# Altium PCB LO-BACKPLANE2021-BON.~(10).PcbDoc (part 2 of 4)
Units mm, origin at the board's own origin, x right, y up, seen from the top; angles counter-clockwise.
Board outline 469.9 x 101.6 mm, 4 copper layers (1, Signal Layer 1, Signal Layer 2, 4), stack 1.53 mm thick; 160 components, 92 nets, 524 pads, 8353 vias.

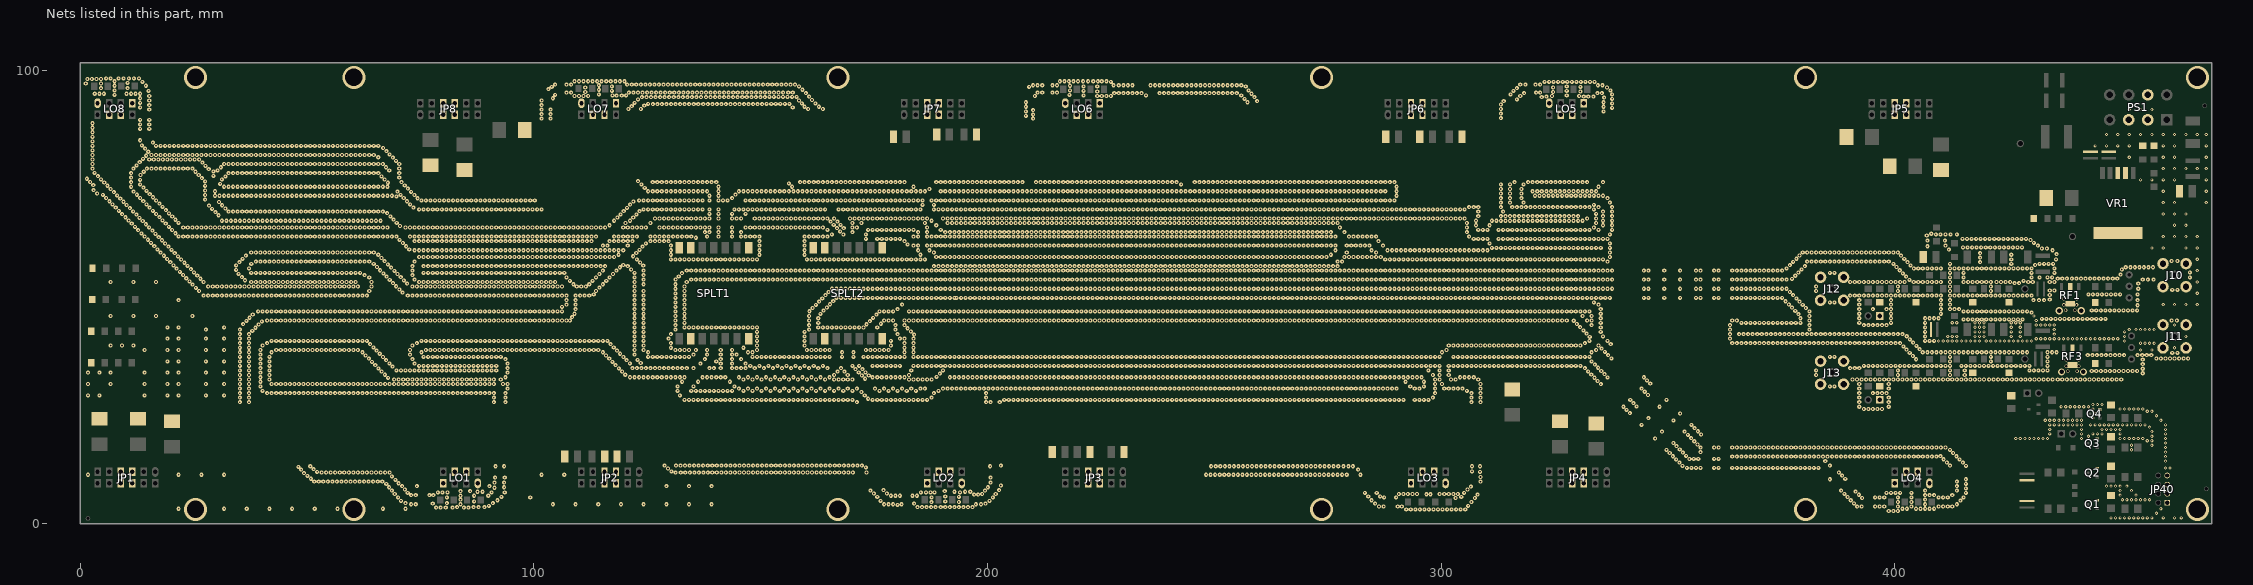
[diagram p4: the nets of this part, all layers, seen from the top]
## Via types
v1: diameter 0.9, hole 0.35, 1 to 4, 7972 vias
v2: diameter 0.7, hole 0.3, 1 to 4, 286 vias
v3: diameter 1.6, hole 1, 1 to 4, 60 vias
v4: diameter 0.762, hole 0.508, 1 to 4, 12 vias
v5: diameter 5.08, hole 3.85, 1 to 4, 12 vias
v6: diameter 2, hole 1.1, 1 to 4, 10 vias
v7: diameter 1.27, hole 0.7, 1 to 4, 1 vias

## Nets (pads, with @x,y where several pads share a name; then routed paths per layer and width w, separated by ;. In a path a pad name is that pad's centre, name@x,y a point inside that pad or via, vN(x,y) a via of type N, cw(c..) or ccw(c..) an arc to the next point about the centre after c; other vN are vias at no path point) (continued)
GND: (continued)
  other v1: 398.7,2.8 399.7,2.8 400.7,2.8 292.325,3.175 293.325,3.175 294.325,3.175 295.325,3.175 296.325,3.175 297.325,3.175 298.325,3.175 299.325,3.175 300.325,3.175 301.325,3.175 302.325,3.175 303.325,3.175 304.325,3.175 305.325,3.175 21.7,3.3 31.7,3.3 36.7,3.3 41.7,3.3 46.7,3.3 51.7,3.3 56.7,3.3 66.7,3.3 71.7,3.3 401.7,3.3 402.7,3.3 404.7,3.3 405.7,3.3 406.7,3.3 407.7,3.3 408.7,3.3 78.45,3.55 79.45,3.55 80.575,3.55 82.075,3.55 84.575,3.55 85.575,3.55 83.075,3.675 86.7,3.675 87.825,3.675 89.075,3.675 184.575,3.675 185.575,3.675 186.575,3.675 187.575,3.675 188.575,3.675 189.7,3.675 190.7,3.675 191.7,3.675 192.7,3.675 193.7,3.675 194.7,3.675 195.7,3.675 196.7,3.675 391.736,3.764 286.325,3.8 287.325,3.8 290.45,3.8 291.325,3.8 392.7,3.8 395.7,3.8 396.7,3.8 397.7,3.8 400.7,3.8 403.7,3.8 409.7,3.8 410.7,3.8 411.7,3.8 412.7,3.8 90.075,3.925 305.95,3.925 180.2,4.175 72.95,4.3 73.95,4.3 83.825,4.3 104.2,4.3 109.2,4.3 114.2,4.3 119.2,4.3 124.2,4.3 129.2,4.3 134.2,4.3 139.2,4.3 177.2,4.3 178.2,4.3 179.2,4.3 181.075,4.3 197.45,4.3 198.575,4.3 406.7,4.3 413.7,4.3 77.7,4.425 183.825,4.425 199.575,4.425 285.45,4.425 391.028,4.472 71.7,4.55 80.825,4.55 90.95,4.55 187.625,4.75 193.7,4.8 306.7,4.8 400.7,4.8 403.7,4.8 86.825,4.925 190.7,4.925 70.7,5.05 176.45,5.05 200.45,5.05 414.493,5.093 91.95,5.175 284.7,5.175 390.321,5.179 83.825,5.3 406.7,5.3 303.2,5.675 307.45,5.675 392.821,5.679 70.075,5.8 80.825,5.8 99.2,5.8 187.7,5.8 201.2,5.8 287.45,5.8 290.075,5.8 395.7,5.8 396.7,5.8 397.7,5.8 400.7,5.8 403.7,5.8 409.7,5.8 410.7,5.8 411.7,5.8 415.2,5.8 389.614,5.886 92.825,5.925 175.7,5.925 193.7,5.925 304.45,5.925 190.7,6.05 283.95,6.05 286.575,6.05 83.825,6.175 86.825,6.175 89.95,6.175 178.7,6.175 179.7,6.175 180.7,6.175 183.45,6.175 184.45,6.175 72.95,6.3 73.95,6.3 76.95,6.3 77.825,6.3 406.7,6.3 407.7,6.3 408.7,6.3 412.7,6.3 392.114,6.386 197.075,6.425 197.95,6.425 308.075,6.425 296.75,6.5 297.625,6.5 69.325,6.55 198.825,6.55 201.825,6.55 290.7,6.55 291.7,6.55 292.7,6.55 293.7,6.55 294.7,6.55 299.7,6.55 300.7,6.55 301.7,6.55 302.7,6.55 303.7,6.55 388.907,6.593 174.95,6.675 177.825,6.675 72.2,6.8 283.2,6.8 285.825,6.8 305.075,6.8 398.2,6.8 399.2,6.8 400.2,6.8 401.2,6.8 403.7,6.8 415.7,6.8 78.825,6.925 79.825,6.925 80.95,6.925 90.7,6.925 93.575,6.925 185.325,6.925 186.45,6.925 187.45,6.925 188.325,6.925 193.95,6.925 87.575,7.05 88.7,7.05 192.7,7.05 195.075,7.05 196.2,7.05 391.407,7.093 83.825,7.175 85.95,7.175 190.575,7.175 68.7,7.3 174.2,7.3 199.45,7.3 388.2,7.3 406.7,7.3 413.7,7.3 177.075,7.425 202.575,7.425 71.575,7.55 305.825,7.55 415.7,7.8 91.325,7.925 68.075,8.05 93.45,8.05 200.075,8.05 306.575,8.175 70.95,8.3 74.2,8.3 90.2,8.3 129.2,8.3 134.2,8.3 139.2,8.3 413.7,8.3 202.95,8.425 67.45,8.8 415.7,8.8 70.2,8.925 91.325,9.05 93.45,9.05 200.7,9.05 51.575,9.3 52.575,9.3 53.575,9.3 54.575,9.3 55.575,9.3 56.575,9.3 57.575,9.3 58.575,9.3 59.575,9.3 60.575,9.3 61.575,9.3 62.575,9.3 63.575,9.3 64.575,9.3 65.575,9.3 66.575,9.3 308.7,9.3 413.7,9.3 69.45,9.675 385.7,9.8 415.7,9.8 389.114,9.886 50.825,9.925 91.45,10.175 93.575,10.175 200.7,10.175 308.7,10.3 68.7,10.425 50.075,10.55 388.407,10.593 1.7,10.8 21.7,10.8 26.7,10.8 31.7,10.8 101.7,10.8 106.7,10.8 248.2,10.8 249.2,10.8 250.2,10.8 251.2,10.8 252.2,10.8 253.2,10.8 254.2,10.8 255.2,10.8 256.2,10.8 257.2,10.8 258.2,10.8 259.2,10.8 260.2,10.8 261.2,10.8 262.2,10.8 263.2,10.8 264.2,10.8 265.2,10.8 266.2,10.8 267.2,10.8 268.2,10.8 269.2,10.8 270.2,10.8 271.2,10.8 272.2,10.8 273.2,10.8 274.2,10.8 275.2,10.8 276.2,10.8 277.2,10.8 278.2,10.8 279.2,10.8 282.2,10.8 49.325,11.175 131.25,11.25 132.375,11.25 133.375,11.25 134.375,11.25 135.375,11.25 136.375,11.25 137.375,11.25 138.375,11.25 53.2,11.3 54.2,11.3 55.2,11.3 56.2,11.3 57.2,11.3 58.2,11.3 59.2,11.3 60.2,11.3 61.2,11.3 62.2,11.3 63.2,11.3 64.2,11.3 65.2,11.3 66.2,11.3 67.2,11.3 68.2,11.3 139.325,11.3 140.325,11.3 141.325,11.3 142.325,11.3 143.325,11.3 144.325,11.3 145.325,11.3 146.325,11.3 147.325,11.3 148.325,11.3 149.325,11.3 150.325,11.3 151.325,11.3 152.325,11.3 153.325,11.3 154.325,11.3 155.325,11.3 156.325,11.3 157.325,11.3 158.325,11.3 159.325,11.3 160.325,11.3 161.325,11.3 162.325,11.3 163.325,11.3 164.325,11.3 165.325,11.3 166.325,11.3 167.325,11.3 168.325,11.3 169.325,11.3 170.325,11.3 173.325,11.3 387.7,11.3 52.2,11.425 308.575,11.425 130.325,11.55 306.825,11.55 48.7,11.925 281.7,11.925 51.45,12.05 129.575,12.175 354.2,12.3 355.2,12.3 356.2,12.3 357.2,12.3 360.2,12.3 361.2,12.3 364.2,12.3 365.2,12.3 366.2,12.3 367.2,12.3 368.2,12.3 369.2,12.3 370.2,12.3 371.2,12.3 372.2,12.3 373.2,12.3 374.2,12.3 375.2,12.3 376.2,12.3 377.2,12.3 378.2,12.3 379.2,12.3 380.2,12.3 381.2,12.3 382.2,12.3 383.2,12.3 173.2,12.425 48.075,12.55 50.7,12.675 91.575,12.675 93.45,12.675 200.575,12.675 249.325,12.675 250.325,12.675 251.325,12.675 252.325,12.675 253.325,12.675 254.325,12.675 255.325,12.675 256.325,12.675 257.325,12.675 258.325,12.675 259.325,12.675 260.325,12.675 261.325,12.675 262.325,12.675 263.325,12.675 264.325,12.675 265.325,12.675 266.325,12.675 267.325,12.675 268.325,12.675 269.325,12.675 270.325,12.675 271.325,12.675 272.325,12.675 273.325,12.675 274.325,12.675 275.325,12.675 276.325,12.675 277.325,12.675 278.45,12.675 279.575,12.675 280.575,12.675 306.825,12.675 308.575,12.675 353.236,12.764 415.736,12.764 128.825,12.8 131.325,12.8 132.325,12.8 133.325,12.8 134.325,12.8 135.325,12.8 136.325,12.8 137.325,12.8 138.325,12.8 139.325,12.8 140.325,12.8 141.325,12.8 142.325,12.8 143.325,12.8 144.325,12.8 145.325,12.8 146.325,12.8 147.325,12.8 148.325,12.8 149.325,12.8 150.325,12.8 151.325,12.8 152.325,12.8 153.325,12.8 154.325,12.8 155.325,12.8 156.325,12.8 157.325,12.8 158.325,12.8 159.325,12.8 160.325,12.8 161.325,12.8 162.325,12.8 163.325,12.8 164.325,12.8 165.325,12.8 166.325,12.8 167.325,12.8 168.325,12.8 169.325,12.8 170.325,12.8 171.325,12.8 172.325,12.8 202.95,12.8 385.7,12.8 412.2,12.8 352.528,13.472 415.028,13.472 411.493,13.507 384.7,13.8 351.821,14.179 414.321,14.179 410.786,14.214 354.736,14.264 355.7,14.3 356.7,14.3 360.2,14.3 361.2,14.3 364.2,14.8 365.2,14.8 366.2,14.8 367.2,14.8 368.2,14.8 369.2,14.8 370.2,14.8 371.2,14.8 372.2,14.8 373.2,14.8 374.2,14.8 375.2,14.8 376.2,14.8 377.2,14.8 378.2,14.8 379.2,14.8 380.2,14.8 381.2,14.8 382.2,14.8 383.2,14.8 384.2,14.8 385.2,14.8 386.2,14.8 387.2,14.8 388.2,14.8 389.2,14.8 390.2,14.8 391.2,14.8 392.2,14.8 393.2,14.8 394.2,14.8 395.2,14.8 396.2,14.8 397.2,14.8 398.2,14.8 399.2,14.8 400.2,14.8 401.2,14.8 402.2,14.8 403.2,14.8 404.2,14.8 405.2,14.8 406.2,14.8 407.2,14.8 408.2,14.8 409.2,14.8 351.114,14.886 413.614,14.886 410.079,14.921 354.028,14.972 350.407,15.593 412.907,15.593 353.321,15.679 357.2,15.8 349.7,16.3 412.2,16.3 352.614,16.386 357.236,16.764 360.2,16.8 361.2,16.8 364.2,16.8 365.2,16.8 366.2,16.8 367.2,16.8 368.2,16.8 369.2,16.8 370.2,16.8 371.2,16.8 372.2,16.8 373.2,16.8 374.2,16.8 375.2,16.8 376.2,16.8 377.2,16.8 378.2,16.8 379.2,16.8 380.2,16.8 381.2,16.8 382.2,16.8 383.2,16.8 384.2,16.8 385.2,16.8 386.2,16.8 387.2,16.8 388.2,16.8 389.2,16.8 390.2,16.8 391.2,16.8 392.2,16.8 393.2,16.8 394.2,16.8 395.2,16.8 396.2,16.8 397.2,16.8 398.2,16.8 399.2,16.8 400.2,16.8 401.2,16.8 402.2,16.8 403.2,16.8 404.2,16.8 405.2,16.8 406.2,16.8 407.2,16.8 408.2,16.8 409.2,16.8 410.2,16.8 411.2,16.8 351.907,17.093 356.528,17.472 351.2,17.8 355.821,18.179 347.2,18.8 355.114,18.886 354.407,19.593 357.321,19.679 348.7,20.3 353.7,20.3 356.614,20.386 355.907,21.093 344.2,21.8 355.2,21.8 351.2,22.8 345.7,23.3 352.7,24.3 341.614,24.386 340.907,25.093 393.2,25.3 394.2,25.3 395.2,25.3 396.2,25.3 397.2,25.3 340.2,25.8 348.2,25.8 392.2,25.8 398.7,25.8 343.114,25.886 342.407,26.593 35.2,26.8 37.2,26.8 91.2,26.8 93.7,26.8 171.2,26.8 199.7,26.8 200.7,26.8 202.7,26.8 392.2,26.8 398.7,26.8 306.7,26.825 308.7,26.825 133.2,27.3 134.2,27.3 135.2,27.3 136.2,27.3 137.2,27.3 138.2,27.3 139.2,27.3 140.2,27.3 141.2,27.3 142.2,27.3 143.2,27.3 144.2,27.3 145.2,27.3 146.2,27.3 147.2,27.3 148.2,27.3 149.2,27.3 150.2,27.3 151.2,27.3 152.2,27.3 153.2,27.3 154.2,27.3 155.2,27.3 156.2,27.3 157.2,27.3 158.2,27.3 159.2,27.3 160.2,27.3 161.2,27.3 162.2,27.3 163.2,27.3 164.2,27.3 165.2,27.3 166.2,27.3 167.2,27.3 168.2,27.3 169.2,27.3 170.2,27.3 174.7,27.3 175.7,27.3 176.7,27.3 177.7,27.3 178.7,27.3 179.7,27.3 180.7,27.3 181.7,27.3 182.7,27.3 183.7,27.3 184.7,27.3 185.7,27.3 186.7,27.3 203.7,27.3 204.7,27.3 205.7,27.3 206.7,27.3 207.7,27.3 208.7,27.3 209.7,27.3 210.7,27.3 211.7,27.3 212.7,27.3 213.7,27.3 214.7,27.3 215.7,27.3 216.7,27.3 217.7,27.3 218.7,27.3 219.7,27.3 220.7,27.3 221.7,27.3 222.7,27.3 223.7,27.3 224.7,27.3 225.7,27.3 226.7,27.3 227.7,27.3 228.7,27.3 229.7,27.3 230.7,27.3 231.7,27.3 232.7,27.3 233.7,27.3 234.7,27.3 235.7,27.3 236.7,27.3 237.7,27.3 238.7,27.3 239.7,27.3 240.7,27.3 241.7,27.3 242.7,27.3 243.7,27.3 244.7,27.3 245.7,27.3 246.7,27.3 247.7,27.3 248.7,27.3 249.7,27.3 250.7,27.3 251.7,27.3 252.7,27.3 253.7,27.3 254.7,27.3 255.7,27.3 256.7,27.3 257.7,27.3 258.7,27.3 259.7,27.3 260.7,27.3 261.7,27.3 262.7,27.3 263.7,27.3 264.7,27.3 265.7,27.3 266.7,27.3 267.7,27.3 268.7,27.3 269.7,27.3 270.7,27.3 271.7,27.3 272.7,27.3 273.7,27.3 274.7,27.3 275.7,27.3 276.7,27.3 277.7,27.3 278.7,27.3 279.7,27.3 280.7,27.3 281.7,27.3 282.7,27.3 283.7,27.3 284.7,27.3 285.7,27.3 286.7,27.3 287.7,27.3 288.7,27.3 289.7,27.3 290.7,27.3 291.7,27.3 294.2,27.3 295.2,27.3 296.2,27.3 297.2,27.3 341.7,27.3 349.7,27.3 173.7,27.55 35.2,27.8 37.2,27.8 91.2,27.8 93.7,27.8 187.7,27.8 199.7,27.8 298.2,27.8 306.7,27.8 308.7,27.8 392.2,27.8 398.7,27.8 1.7,28.3 4.2,28.3 14.2,28.3 19.2,28.3 21.7,28.3 27.7,28.3 31.7,28.3 132.2,28.3 172.95,28.3 345.614,28.386 35.2,28.8 37.2,28.8 41.2,28.8 42.2,28.8 43.2,28.8 44.2,28.8 45.2,28.8 46.2,28.8 47.2,28.8 48.2,28.8 49.2,28.8 50.2,28.8 51.2,28.8 52.2,28.8 53.2,28.8 54.2,28.8 55.2,28.8 56.2,28.8 57.2,28.8 58.2,28.8 59.2,28.8 60.2,28.8 61.2,28.8 62.2,28.8 63.2,28.8 64.2,28.8 65.2,28.8 66.2,28.8 67.2,28.8 68.2,28.8 69.2,28.8 70.2,28.8 71.2,28.8 72.2,28.8 73.2,28.8 74.2,28.8 75.2,28.8 76.2,28.8 77.2,28.8 78.2,28.8 79.2,28.8 80.2,28.8 81.2,28.8 82.2,28.8 83.2,28.8 84.2,28.8 85.2,28.8 86.2,28.8 87.2,28.8 88.2,28.8 89.2,28.8 90.2,28.8 91.2,28.8 93.7,28.8 188.2,28.8 199.7,28.8 298.7,28.8 306.7,28.8 308.7,28.8 392.2,28.8 395.2,28.8 396.2,28.8 397.2,28.8 398.2,28.8 172.2,29.05 344.907,29.093 40.2,29.3 131.7,29.3 134.7,29.3 135.7,29.3 136.7,29.3 137.7,29.3 138.7,29.3 139.7,29.3 140.7,29.3 141.7,29.3 142.7,29.3 143.7,29.3 146.2,29.3 148.2,29.3 150.2,29.3 152.2,29.3 154.2,29.3 156.2,29.3 158.2,29.3 160.2,29.3 162.2,29.3 164.2,29.3 166.2,29.3 168.2,29.3 170.2,29.3 176.2,29.3 178.2,29.3 180.2,29.3 182.2,29.3 184.2,29.3 189.2,29.3 305.7,29.3 35.2,29.8 37.2,29.8 94.2,29.8 145.2,29.8 147.2,29.8 149.2,29.8 151.2,29.8 153.2,29.8 155.2,29.8 157.2,29.8 159.2,29.8 161.2,29.8 163.2,29.8 165.2,29.8 167.2,29.8 169.2,29.8 171.2,29.8 175.2,29.8 177.2,29.8 179.2,29.8 181.2,29.8 183.2,29.8 185.2,29.8 186.2,29.8 190.2,29.8 191.2,29.8 192.2,29.8 193.2,29.8 194.2,29.8 195.2,29.8 196.2,29.8 197.2,29.8 198.2,29.8 199.2,29.8 200.2,29.8 201.2,29.8 202.2,29.8 203.2,29.8 204.2,29.8 205.2,29.8 206.2,29.8 207.2,29.8 208.2,29.8 209.2,29.8 210.2,29.8 211.2,29.8 212.2,29.8 213.2,29.8 214.2,29.8 215.2,29.8 216.2,29.8 217.2,29.8 218.2,29.8 219.2,29.8 220.2,29.8 221.2,29.8 222.2,29.8 223.2,29.8 224.2,29.8 225.2,29.8 226.2,29.8 227.2,29.8 228.2,29.8 229.2,29.8 230.2,29.8 231.2,29.8 232.2,29.8 233.2,29.8 234.2,29.8 235.2,29.8 236.2,29.8 237.2,29.8 238.2,29.8 239.2,29.8 240.2,29.8 241.2,29.8 242.2,29.8 243.2,29.8 244.2,29.8 245.2,29.8 246.2,29.8 247.2,29.8 248.2,29.8 249.2,29.8 250.2,29.8 251.2,29.8 252.2,29.8 253.2,29.8 254.2,29.8 255.2,29.8 256.2,29.8 257.2,29.8 258.2,29.8 259.2,29.8 260.2,29.8 261.2,29.8 262.2,29.8 263.2,29.8 264.2,29.8 265.2,29.8 266.2,29.8 267.2,29.8 268.2,29.8 269.2,29.8 270.2,29.8 271.2,29.8 272.2,29.8 273.2,29.8 274.2,29.8 275.2,29.8 276.2,29.8 277.2,29.8 278.2,29.8 279.2,29.8 280.2,29.8 281.2,29.8 282.2,29.8 283.2,29.8 284.2,29.8 285.2,29.8 286.2,29.8 287.2,29.8 288.2,29.8 289.2,29.8 290.2,29.8 294.2,29.8 295.2,29.8 298.7,29.8 300.7,29.8 301.7,29.8 302.7,29.8 303.7,29.8 304.7,29.8 308.7,29.8 344.2,29.8 392.2,29.8 398.7,29.8 39.7,30.3 131.7,30.3 135.2,30.3 144.2,30.3 293.2,30.3 296.2,30.3 385.7,30.3 386.7,30.3 335.236,30.764 1.7,30.8 6.7,30.8 14.2,30.8 19.2,30.8 21.7,30.8 27.7,30.8 31.7,30.8 35.2,30.8 37.2,30.8 42.2,30.8 43.2,30.8 44.2,30.8 45.2,30.8 46.2,30.8 47.2,30.8 48.2,30.8 49.2,30.8 50.2,30.8 51.2,30.8 52.2,30.8 53.2,30.8 54.2,30.8 55.2,30.8 56.2,30.8 57.2,30.8 58.2,30.8 59.2,30.8 60.2,30.8 61.2,30.8 62.2,30.8 63.2,30.8 64.2,30.8 65.2,30.8 66.2,30.8 67.2,30.8 68.2,30.8 69.2,30.8 70.2,30.8 71.2,30.8 72.2,30.8 73.2,30.8 74.2,30.8 75.2,30.8 76.2,30.8 77.2,30.8 78.2,30.8 79.2,30.8 80.2,30.8 81.2,30.8 82.2,30.8 83.2,30.8 84.2,30.8 85.2,30.8 86.2,30.8 87.2,30.8 88.2,30.8 89.2,30.8 90.2,30.8 91.2,30.8 93.2,30.8 94.2,30.8 298.7,30.8 300.2,30.8 308.7,30.8 392.2,30.8 398.7,30.8 346.114,30.886 39.7,31.3 132.7,31.3 136.2,31.3 143.2,31.3 292.2,31.3 296.2,31.3 334.528,31.472 345.407,31.593 35.2,31.8 37.2,31.8 41.7,31.8 69.2,31.8 70.2,31.8 71.2,31.8 72.2,31.8 73.2,31.8 74.2,31.8 75.2,31.8 76.2,31.8 77.2,31.8 78.2,31.8 79.2,31.8 80.2,31.8 81.2,31.8 82.2,31.8 83.2,31.8 84.2,31.8 85.2,31.8 86.2,31.8 87.2,31.8 88.2,31.8 89.2,31.8 90.2,31.8 91.2,31.8 92.7,31.8 146.2,31.8 148.2,31.8 150.2,31.8 152.2,31.8 154.2,31.8 156.2,31.8 158.2,31.8 160.2,31.8 162.2,31.8 164.2,31.8 166.2,31.8 167.2,31.8 168.2,31.8 169.2,31.8 170.2,31.8 182.7,31.8 183.7,31.8 184.7,31.8 185.7,31.8 186.7,31.8 187.7,31.8 298.7,31.8 299.7,31.8 302.2,31.8 303.2,31.8 308.2,31.8 390.7,31.8 391.7,31.8 392.7,31.8 393.7,31.8 394.7,31.8 395.7,31.8 396.7,31.8 397.7,31.8 398.7,31.8 399.7,31.8 400.7,31.8 401.7,31.8 402.7,31.8 403.7,31.8 404.7,31.8 405.7,31.8 406.7,31.8 407.7,31.8 408.7,31.8 409.7,31.8 410.7,31.8 411.7,31.8 412.7,31.8 413.7,31.8 414.7,31.8 415.7,31.8 416.7,31.8 417.7,31.8 418.7,31.8 419.7,31.8 420.825,31.8 421.825,31.8 422.825,31.8 423.825,31.8 424.825,31.8 425.825,31.8 426.825,31.8 427.825,31.8 428.825,31.8 429.825,31.8 430.825,31.8 431.825,31.8 432.825,31.8 433.825,31.8 434.825,31.8 435.95,31.8 436.95,31.8 437.95,31.8 438.95,31.8 439.95,31.8 440.95,31.8 441.95,31.8 442.95,31.8 443.95,31.8 444.95,31.8 445.95,31.8 446.95,31.8 447.95,31.8 448.95,31.8 449.95,31.8 173.028,31.972 67.857,32.143 333.821,32.179 336.736,32.264 39.7,32.3 93.7,32.3 121.2,32.3 122.2,32.3 123.2,32.3 124.2,32.3 125.2,32.3 126.2,32.3 127.2,32.3 128.2,32.3 129.2,32.3 130.2,32.3 131.2,32.3 132.2,32.3 133.2,32.3 137.2,32.3 138.2,32.3 139.2,32.3 140.2,32.3 141.2,32.3 142.2,32.3 145.2,32.3 147.2,32.3 149.2,32.3 151.2,32.3 153.2,32.3 155.2,32.3 157.2,32.3 159.2,32.3 161.2,32.3 163.2,32.3 165.2,32.3 174.7,32.3 175.7,32.3 176.7,32.3 177.7,32.3 178.7,32.3 179.7,32.3 180.7,32.3 181.7,32.3 191.7,32.3 192.7,32.3 193.7,32.3 194.7,32.3 195.7,32.3 196.7,32.3 197.7,32.3 198.7,32.3 199.7,32.3 200.7,32.3 201.7,32.3 202.7,32.3 203.7,32.3 204.7,32.3 205.7,32.3 206.7,32.3 207.7,32.3 208.7,32.3 209.7,32.3 210.7,32.3 211.7,32.3 212.7,32.3 213.7,32.3 214.7,32.3 215.7,32.3 216.7,32.3 217.7,32.3 218.7,32.3 219.7,32.3 220.7,32.3 221.7,32.3 222.7,32.3 223.7,32.3 224.7,32.3 225.7,32.3 226.7,32.3 227.7,32.3 228.7,32.3 229.7,32.3 230.7,32.3 231.7,32.3 232.7,32.3 233.7,32.3 234.7,32.3 235.7,32.3 236.7,32.3 237.7,32.3 238.7,32.3 239.7,32.3 240.7,32.3 241.7,32.3 242.7,32.3 243.7,32.3 244.7,32.3 245.7,32.3 246.7,32.3 247.7,32.3 248.7,32.3 249.7,32.3 250.7,32.3 251.7,32.3 252.7,32.3 253.7,32.3 254.7,32.3 255.7,32.3 256.7,32.3 257.7,32.3 258.7,32.3 259.7,32.3 260.7,32.3 261.7,32.3 262.7,32.3 263.7,32.3 264.7,32.3 265.7,32.3 266.7,32.3 267.7,32.3 268.7,32.3 269.7,32.3 270.7,32.3 271.7,32.3 272.7,32.3 273.7,32.3 274.7,32.3 275.7,32.3 276.7,32.3 277.7,32.3 278.7,32.3 279.7,32.3 280.7,32.3 281.7,32.3 282.7,32.3 283.7,32.3 284.7,32.3 285.7,32.3 286.7,32.3 287.7,32.3 288.7,32.3 289.7,32.3 290.7,32.3 291.7,32.3 292.7,32.3 293.7,32.3 294.7,32.3 295.7,32.3 304.2,32.3 305.2,32.3 306.2,32.3 307.2,32.3 344.7,32.3 188.786,32.386 172.321,32.679 173.821,32.679 35.2,32.8 37.2,32.8 41.7,32.8 166.2,32.8 169.2,32.8 182.7,32.8 298.2,32.8 299.7,32.8 301.7,32.8 382.7,32.8 400.7,32.8 412.2,32.8 415.45,32.8 67.15,32.85 120.15,32.85 333.114,32.886 336.028,32.972 189.493,33.093 454.7,33.175 1.7,33.3 4.2,33.3 6.7,33.3 14.2,33.3 19.2,33.3 21.7,33.3 27.7,33.3 31.7,33.3 39.7,33.3 94.2,33.3 171.614,33.386 173.114,33.386 66.443,33.557 119.443,33.557 166.95,33.55 168.45,33.55 332.407,33.593 335.321,33.679 443.45,33.675 444.45,33.675 445.45,33.675 446.45,33.675 447.45,33.675 448.45,33.675 449.45,33.675 450.45,33.675 451.45,33.675 452.45,33.675 453.45,33.675 35.2,33.8 37.2,33.8 41.7,33.8 69.7,33.8 70.7,33.8 71.7,33.8 72.7,33.8 73.7,33.8 74.7,33.8 75.7,33.8 76.7,33.8 77.7,33.8 78.7,33.8 79.7,33.8 80.7,33.8 81.7,33.8 82.7,33.8 83.7,33.8 84.7,33.8 85.7,33.8 86.7,33.8 87.7,33.8 88.7,33.8 89.7,33.8 90.7,33.8 91.7,33.8 183.2,33.8 190.2,33.8 297.2,33.8 299.7,33.8 301.7,33.8 382.7,33.8 400.7,33.8 412.2,33.8 415.45,33.8 429.7,33.8 430.7,33.8 431.7,33.8 432.7,33.8 433.7,33.8 170.907,34.093 172.407,34.093 454.7,34.175 65.736,34.264 118.736,34.264 39.7,34.3 94.2,34.3 121.7,34.3 122.7,34.3 123.7,34.3 124.7,34.3 125.7,34.3 126.7,34.3 127.7,34.3 128.7,34.3 129.7,34.3 130.7,34.3 131.7,34.3 132.7,34.3 133.7,34.3 135.2,34.3 138.7,34.3 139.7,34.3 141.2,34.3 143.7,34.3 144.7,34.3 145.7,34.3 146.7,34.3 148.7,34.3 150.7,34.3 152.7,34.3 154.7,34.3 156.7,34.3 158.7,34.3 160.7,34.3 162.7,34.3 164.7,34.3 167.7,34.3 331.7,34.3 390.2,34.3 391.2,34.3 392.2,34.3 334.614,34.386 68.857,34.643 35.2,34.8 37.2,34.8 41.7,34.8 74.7,34.8 75.7,34.8 76.7,34.8 77.7,34.8 78.7,34.8 79.7,34.8 80.7,34.8 81.7,34.8 82.7,34.8 83.7,34.8 84.7,34.8 85.7,34.8 86.7,34.8 87.7,34.8 88.7,34.8 89.7,34.8 90.7,34.8 91.7,34.8 147.7,34.8 149.7,34.8 151.7,34.8 153.7,34.8 155.7,34.8 157.7,34.8 159.7,34.8 161.7,34.8 163.7,34.8 170.2,34.8 171.7,34.8 174.7,34.8 175.7,34.8 176.7,34.8 177.7,34.8 178.7,34.8 179.7,34.8 180.7,34.8 183.7,34.8 184.7,34.8 185.7,34.8 186.7,34.8 187.7,34.8 188.7,34.8 189.7,34.8 190.7,34.8 191.7,34.8 192.7,34.8 193.7,34.8 194.7,34.8 195.7,34.8 196.7,34.8 197.7,34.8 198.7,34.8 199.7,34.8 200.7,34.8 201.7,34.8 202.7,34.8 203.7,34.8 204.7,34.8 205.7,34.8 206.7,34.8 207.7,34.8 208.7,34.8 209.7,34.8 210.7,34.8 211.7,34.8 212.7,34.8 213.7,34.8 214.7,34.8 215.7,34.8 216.7,34.8 217.7,34.8 218.7,34.8 219.7,34.8 220.7,34.8 221.7,34.8 222.7,34.8 223.7,34.8 224.7,34.8 225.7,34.8 226.7,34.8 227.7,34.8 228.7,34.8 229.7,34.8 230.7,34.8 231.7,34.8 232.7,34.8 233.7,34.8 234.7,34.8 235.7,34.8 236.7,34.8 237.7,34.8 238.7,34.8 239.7,34.8 240.7,34.8 241.7,34.8 242.7,34.8 243.7,34.8 244.7,34.8 245.7,34.8 246.7,34.8 247.7,34.8 248.7,34.8 249.7,34.8 250.7,34.8 251.7,34.8 252.7,34.8 253.7,34.8 254.7,34.8 255.7,34.8 256.7,34.8 257.7,34.8 258.7,34.8 259.7,34.8 260.7,34.8 261.7,34.8 262.7,34.8 263.7,34.8 264.7,34.8 265.7,34.8 266.7,34.8 267.7,34.8 268.7,34.8 269.7,34.8 270.7,34.8 271.7,34.8 272.7,34.8 273.7,34.8 274.7,34.8 275.7,34.8 276.7,34.8 277.7,34.8 278.7,34.8 279.7,34.8 280.7,34.8 281.7,34.8 282.7,34.8 283.7,34.8 284.7,34.8 285.7,34.8 286.7,34.8 287.7,34.8 288.7,34.8 289.7,34.8 290.7,34.8 291.7,34.8 292.7,34.8 293.7,34.8 294.7,34.8 295.7,34.8 296.7,34.8 297.7,34.8 298.7,34.8 299.7,34.8 301.7,34.8 302.7,34.8 303.7,34.8 304.7,34.8 305.7,34.8 306.7,34.8 307.7,34.8 308.7,34.8 309.7,34.8 310.7,34.8 311.7,34.8 312.7,34.8 313.7,34.8 314.7,34.8 315.7,34.8 316.7,34.8 317.7,34.8 318.7,34.8 319.7,34.8 320.7,34.8 321.7,34.8 322.7,34.8 323.7,34.8 324.7,34.8 325.7,34.8 326.7,34.8 327.7,34.8 328.7,34.8 329.7,34.8 330.7,34.8 393.2,34.8 394.2,34.8 395.2,34.8 396.2,34.8 397.2,34.8 398.2,34.8 399.2,34.8 400.2,34.8 401.2,34.8 402.2,34.8 403.2,34.8 404.2,34.8 405.2,34.8 406.2,34.8 407.2,34.8 408.2,34.8 409.2,34.8 410.2,34.8 411.2,34.8 412.2,34.8 414.7,34.8 415.7,34.8 416.7,34.8 417.7,34.8 418.7,34.8 419.7,34.8 420.7,34.8 421.7,34.8 422.7,34.8 423.7,34.8 424.7,34.8 425.7,34.8 426.7,34.8 427.7,34.8 428.7,34.8 429.7,34.8 433.7,34.8 65.028,34.972 118.028,34.972 333.907,35.093 454.7,35.175 39.7,35.3 73.7,35.3 94.2,35.3 136.7,35.3 141.2,35.3 143.7,35.3 146.7,35.3 68.15,35.35 121.15,35.35 123.564,35.436 64.321,35.679 117.321,35.679 19.2,35.8 21.7,35.8 27.7,35.8 31.7,35.8 35.2,35.8 37.2,35.8 41.7,35.8 140.2,35.8 333.2,35.8 412.2,35.8 421.2,35.8 433.7,35.8 67.443,36.057 120.443,36.057 122.857,36.143 454.7,36.175 404.736,36.264 39.7,36.3 73.2,36.3 93.7,36.3 137.7,36.3 141.2,36.3 143.7,36.3 145.7,36.3 63.614,36.386 116.614,36.386 457.7,36.425 458.7,36.425 459.7,36.425 460.7,36.425 461.7,36.425 462.7,36.425 463.7,36.425 464.7,36.425 337.528,36.472 66.736,36.764 119.736,36.764 35.2,36.8 37.2,36.8 41.7,36.8 75.7,36.8 76.7,36.8 77.7,36.8 78.7,36.8 79.7,36.8 80.7,36.8 81.7,36.8 82.7,36.8 83.7,36.8 84.7,36.8 85.7,36.8 86.7,36.8 87.7,36.8 88.7,36.8 89.7,36.8 90.7,36.8 91.7,36.8 92.7,36.8 125.2,36.8 126.2,36.8 127.2,36.8 128.2,36.8 129.2,36.8 130.2,36.8 131.2,36.8 132.2,36.8 133.2,36.8 134.2,36.8 148.2,36.8 149.2,36.8 150.2,36.8 151.2,36.8 152.2,36.8 153.2,36.8 154.2,36.8 155.2,36.8 156.2,36.8 157.2,36.8 158.2,36.8 159.2,36.8 160.2,36.8 161.2,36.8 162.2,36.8 163.2,36.8 164.2,36.8 165.2,36.8 167.95,36.8 170.45,36.8 172.7,36.8 173.7,36.8 174.7,36.8 175.7,36.8 176.7,36.8 177.7,36.8 178.7,36.8 179.7,36.8 180.7,36.8 181.7,36.8 183.7,36.8 184.7,36.8 185.7,36.8 186.7,36.8 187.7,36.8 188.7,36.8 189.7,36.8 190.7,36.8 191.7,36.8 192.7,36.8 193.7,36.8 194.7,36.8 195.7,36.8 196.7,36.8 197.7,36.8 198.7,36.8 199.7,36.8 200.7,36.8 201.7,36.8 202.7,36.8 203.7,36.8 204.7,36.8 205.7,36.8 206.7,36.8 207.7,36.8 208.7,36.8 209.7,36.8 210.7,36.8 211.7,36.8 212.7,36.8 213.7,36.8 214.7,36.8 215.7,36.8 216.7,36.8 217.7,36.8 218.7,36.8 219.7,36.8 220.7,36.8 221.7,36.8 222.7,36.8 223.7,36.8 224.7,36.8 225.7,36.8 226.7,36.8 227.7,36.8 228.7,36.8 229.7,36.8 230.7,36.8 231.7,36.8 232.7,36.8 233.7,36.8 234.7,36.8 235.7,36.8 236.7,36.8 237.7,36.8 238.7,36.8 239.7,36.8 240.7,36.8 241.7,36.8 242.7,36.8 243.7,36.8 244.7,36.8 245.7,36.8 246.7,36.8 247.7,36.8 248.7,36.8 249.7,36.8 250.7,36.8 251.7,36.8 252.7,36.8 253.7,36.8 254.7,36.8 255.7,36.8 256.7,36.8 257.7,36.8 258.7,36.8 259.7,36.8 260.7,36.8 261.7,36.8 262.7,36.8 263.7,36.8 264.7,36.8 265.7,36.8 266.7,36.8 267.7,36.8 268.7,36.8 269.7,36.8 270.7,36.8 271.7,36.8 272.7,36.8 273.7,36.8 274.7,36.8 275.7,36.8 276.7,36.8 277.7,36.8 278.7,36.8 279.7,36.8 280.7,36.8 281.7,36.8 282.7,36.8 283.7,36.8 284.7,36.8 285.7,36.8 286.7,36.8 287.7,36.8 288.7,36.8 289.7,36.8 290.7,36.8 291.7,36.8 292.7,36.8 293.7,36.8 294.7,36.8 295.7,36.8 296.7,36.8 297.7,36.8 298.7,36.8 299.7,36.8 302.7,36.8 303.7,36.8 304.7,36.8 305.7,36.8 306.7,36.8 307.7,36.8 308.7,36.8 309.7,36.8 310.7,36.8 311.7,36.8 312.7,36.8 313.7,36.8 314.7,36.8 315.7,36.8 316.7,36.8 317.7,36.8 318.7,36.8 319.7,36.8 320.7,36.8 321.7,36.8 322.7,36.8 323.7,36.8 324.7,36.8 325.7,36.8 326.7,36.8 327.7,36.8 328.7,36.8 329.7,36.8 330.7,36.8 331.7,36.8 332.7,36.8 385.7,36.8 386.7,36.8 412.2,36.8 421.2,36.8 433.7,36.8 404.028,36.972 62.907,37.093 115.907,37.093 336.821,37.179 442.575,37.175 443.575,37.175 444.575,37.175 445.575,37.175 446.575,37.175 447.575,37.175 448.575,37.175 449.575,37.175 450.575,37.175 453.575,37.175 454.575,37.175 455.575,37.175 456.575,37.175 39.7,37.3 72.7,37.3 122.2,37.3 135.2,37.3 138.2,37.3 141.2,37.3 143.7,37.3 144.7,37.3 66.028,37.472 119.028,37.472 403.321,37.679 461.2,37.675 462.325,37.675 35.2,37.8 37.2,37.8 42.2,37.8 62.2,37.8 75.2,37.8 115.2,37.8 125.2,37.8 147.2,37.8 148.2,37.8 167.95,37.8 170.45,37.8 181.7,37.8 183.7,37.8 300.2,37.8 333.2,37.8 406.2,37.8 407.2,37.8 408.2,37.8 409.2,37.8 410.2,37.8 411.2,37.8 412.2,37.8 413.2,37.8 414.2,37.8 415.2,37.8 416.2,37.8 417.2,37.8 418.2,37.8 419.2,37.8 420.2,37.8 421.2,37.8 422.2,37.8 423.2,37.8 424.2,37.8 425.2,37.8 426.2,37.8 427.2,37.8 428.2,37.8 429.2,37.8 433.7,37.8 434.7,37.8 435.7,37.8 336.114,37.886 65.321,38.179 118.321,38.179 14.2,38.3 19.2,38.3 21.7,38.3 27.7,38.3 31.7,38.3 39.7,38.3 43.2,38.3 44.2,38.3 45.2,38.3 46.2,38.3 47.2,38.3 48.2,38.3 49.2,38.3 50.2,38.3 51.2,38.3 52.2,38.3 53.2,38.3 54.2,38.3 55.2,38.3 56.2,38.3 57.2,38.3 58.2,38.3 59.2,38.3 60.2,38.3 61.2,38.3 72.7,38.3 76.2,38.3 77.2,38.3 78.2,38.3 79.2,38.3 80.2,38.3 81.2,38.3 82.2,38.3 83.2,38.3 84.2,38.3 85.2,38.3 86.2,38.3 87.2,38.3 88.2,38.3 89.2,38.3 90.2,38.3 91.2,38.3 92.2,38.3 93.2,38.3 94.2,38.3 95.2,38.3 96.2,38.3 97.2,38.3 98.2,38.3 99.2,38.3 100.2,38.3 101.2,38.3 102.2,38.3 103.2,38.3 104.2,38.3 105.2,38.3 106.2,38.3 107.2,38.3 108.2,38.3 109.2,38.3 110.2,38.3 111.2,38.3 112.2,38.3 113.2,38.3 114.2,38.3 122.2,38.3 124.2,38.3 131.2,38.3 132.2,38.3 133.2,38.3 134.2,38.3 135.7,38.3 138.2,38.3 141.2,38.3 143.7,38.3 149.2,38.3 160.2,38.3 161.2,38.3 162.2,38.3 163.2,38.3 164.2,38.3 165.2,38.3 173.2,38.3 174.2,38.3 175.2,38.3 176.2,38.3 177.2,38.3 178.2,38.3 301.2,38.3 334.2,38.3 402.614,38.386 405.493,38.507 335.407,38.593 35.2,38.8 37.2,38.8 130.2,38.8 146.2,38.8 181.7,38.8 183.7,38.8 64.614,38.886 117.614,38.886 401.907,39.093 404.786,39.214 6.7,39.3 9.2,39.3 11.7,39.3 40.2,39.3 73.2,39.3 122.2,39.3 124.2,39.3 149.2,39.3 159.7,39.3 178.7,39.3 301.7,39.3 302.7,39.3 303.7,39.3 304.7,39.3 305.7,39.3 306.7,39.3 307.7,39.3 308.7,39.3 309.7,39.3 310.7,39.3 311.7,39.3 312.7,39.3 313.7,39.3 314.7,39.3 315.7,39.3 316.7,39.3 317.7,39.3 318.7,39.3 319.7,39.3 320.7,39.3 321.7,39.3 322.7,39.3 323.7,39.3 324.7,39.3 325.7,39.3 326.7,39.3 327.7,39.3 328.7,39.3 329.7,39.3 330.7,39.3 334.7,39.3 63.907,39.593 116.907,39.593 337.407,39.593 35.2,39.8 37.2,39.8 41.2,39.8 74.2,39.8 130.2,39.8 181.7,39.8 183.7,39.8 331.7,39.8 364.2,39.8 365.2,39.8 366.2,39.8 367.2,39.8 368.2,39.8 369.2,39.8 370.2,39.8 371.2,39.8 372.2,39.8 373.2,39.8 374.2,39.8 375.2,39.8 376.2,39.8 377.2,39.8 378.2,39.8 379.2,39.8 380.2,39.8 381.2,39.8 382.2,39.8 383.2,39.8 384.2,39.8 385.2,39.8 386.2,39.8 387.2,39.8 388.2,39.8 389.2,39.8 390.2,39.8 391.2,39.8 392.2,39.8 393.2,39.8 394.2,39.8 395.2,39.8 396.2,39.8 397.2,39.8 398.2,39.8 399.2,39.8 400.2,39.8 401.2,39.8 404.079,39.921 42.2,40.3 43.2,40.3 44.2,40.3 45.2,40.3 46.2,40.3 47.2,40.3 48.2,40.3 49.2,40.3 50.2,40.3 51.2,40.3 52.2,40.3 53.2,40.3 54.2,40.3 55.2,40.3 56.2,40.3 57.2,40.3 58.2,40.3 59.2,40.3 60.2,40.3 61.2,40.3 62.2,40.3 63.2,40.3 75.2,40.3 76.2,40.3 77.2,40.3 78.2,40.3 79.2,40.3 80.2,40.3 81.2,40.3 82.2,40.3 83.2,40.3 84.2,40.3 85.2,40.3 86.2,40.3 87.2,40.3 88.2,40.3 89.2,40.3 90.2,40.3 91.2,40.3 92.2,40.3 93.2,40.3 94.2,40.3 95.2,40.3 96.2,40.3 97.2,40.3 98.2,40.3 99.2,40.3 100.2,40.3 101.2,40.3 102.2,40.3 103.2,40.3 104.2,40.3 105.2,40.3 106.2,40.3 107.2,40.3 108.2,40.3 109.2,40.3 110.2,40.3 111.2,40.3 112.2,40.3 113.2,40.3 114.2,40.3 115.2,40.3 116.2,40.3 122.2,40.3 124.2,40.3 149.2,40.3 159.7,40.3 178.7,40.3 332.7,40.3 336.7,40.3 406.7,40.3 407.7,40.3 408.7,40.3 403.372,40.628 19.2,40.8 21.7,40.8 27.7,40.8 31.7,40.8 35.2,40.8 37.2,40.8 129.7,40.8 180.7,40.8 181.7,40.8 183.7,40.8 363.7,40.8 332.786,41.214 122.2,41.3 124.2,41.3 149.2,41.3 159.7,41.3 335.7,41.3 406.7,41.3 402.664,41.336 183.821,41.679 35.2,41.8 37.2,41.8 130.2,41.8 180.2,41.8 363.7,41.8 365.7,41.8 366.7,41.8 367.7,41.8 368.7,41.8 369.7,41.8 370.7,41.8 371.7,41.8 372.7,41.8 373.7,41.8 374.7,41.8 375.7,41.8 376.7,41.8 377.7,41.8 378.7,41.8 379.7,41.8 380.7,41.8 381.7,41.8 382.7,41.8 383.7,41.8 384.7,41.8 385.7,41.8 386.7,41.8 387.7,41.8 388.7,41.8 389.7,41.8 390.7,41.8 391.7,41.8 392.7,41.8 393.7,41.8 394.7,41.8 395.7,41.8 396.7,41.8 397.7,41.8 398.7,41.8 399.7,41.8 400.7,41.8 401.7,41.8 332.079,41.921 122.2,42.3 124.2,42.3 149.2,42.3 159.7,42.3 335.2,42.3 406.7,42.3 183.114,42.386 37.907,42.507 331.372,42.628 27.7,42.8 35.2,42.8 131.2,42.8 160.7,42.8 179.7,42.8 363.7,42.8 381.2,42.8 182.407,43.093 38.614,43.214 172.664,43.264 19.2,43.3 21.7,43.3 31.7,43.3 122.2,43.3 124.2,43.3 133.2,43.3 134.2,43.3 135.2,43.3 136.2,43.3 137.2,43.3 138.2,43.3 139.2,43.3 140.2,43.3 141.2,43.3 142.2,43.3 143.2,43.3 144.2,43.3 145.2,43.3 146.2,43.3 147.2,43.3 148.2,43.3 149.2,43.3 162.7,43.3 163.7,43.3 164.7,43.3 165.7,43.3 166.7,43.3 167.7,43.3 168.7,43.3 169.7,43.3 170.7,43.3 171.7,43.3 175.7,43.3 335.2,43.3 406.7,43.3 330.664,43.336 131.2,43.8 160.7,43.8 179.7,43.8 181.7,43.8 333.2,43.8 363.7,43.8 381.2,43.8 393.2,43.8 394.2,43.8 395.2,43.8 396.2,43.8 397.2,43.8 398.2,43.8 39.321,43.921 173.372,43.972 35.907,44.007 329.957,44.043 176.493,44.093 122.2,44.3 124.2,44.3 133.2,44.3 162.7,44.3 335.2,44.3 366.2,44.3 367.2,44.3 368.2,44.3 369.2,44.3 370.2,44.3 371.2,44.3 372.2,44.3 373.2,44.3 374.2,44.3 375.2,44.3 376.2,44.3 377.2,44.3 378.2,44.3 379.2,44.3 392.2,44.3 399.2,44.3 406.7,44.3 40.028,44.628 174.079,44.679 36.614,44.714 329.25,44.75 41.2,44.8 42.2,44.8 43.2,44.8 44.2,44.8 45.2,44.8 46.2,44.8 47.2,44.8 48.2,44.8 49.2,44.8 50.2,44.8 51.2,44.8 52.2,44.8 53.2,44.8 54.2,44.8 55.2,44.8 56.2,44.8 57.2,44.8 58.2,44.8 59.2,44.8 60.2,44.8 61.2,44.8 62.2,44.8 63.2,44.8 64.2,44.8 65.2,44.8 66.2,44.8 67.2,44.8 68.2,44.8 69.2,44.8 70.2,44.8 71.2,44.8 72.2,44.8 73.2,44.8 74.2,44.8 75.2,44.8 76.2,44.8 77.2,44.8 78.2,44.8 79.2,44.8 80.2,44.8 81.2,44.8 82.2,44.8 83.2,44.8 84.2,44.8 85.2,44.8 86.2,44.8 87.2,44.8 88.2,44.8 89.2,44.8 90.2,44.8 91.2,44.8 92.2,44.8 93.2,44.8 94.2,44.8 95.2,44.8 96.2,44.8 97.2,44.8 98.2,44.8 99.2,44.8 100.2,44.8 101.2,44.8 102.2,44.8 103.2,44.8 104.2,44.8 105.2,44.8 106.2,44.8 107.2,44.8 107.95,44.8 131.2,44.8 160.7,44.8 177.2,44.8 178.2,44.8 179.2,44.8 181.7,44.8 182.7,44.8 183.7,44.8 184.7,44.8 185.7,44.8 186.7,44.8 187.7,44.8 188.7,44.8 189.7,44.8 190.7,44.8 191.7,44.8 192.7,44.8 193.7,44.8 194.7,44.8 195.7,44.8 196.7,44.8 197.7,44.8 198.7,44.8 199.7,44.8 200.7,44.8 201.7,44.8 202.7,44.8 203.7,44.8 204.7,44.8 205.7,44.8 206.7,44.8 207.7,44.8 208.7,44.8 209.7,44.8 210.7,44.8 211.7,44.8 212.7,44.8 213.7,44.8 214.7,44.8 215.7,44.8 216.7,44.8 217.7,44.8 218.7,44.8 219.7,44.8 220.7,44.8 221.7,44.8 222.7,44.8 223.7,44.8 224.7,44.8 225.7,44.8 226.7,44.8 227.7,44.8 228.7,44.8 229.7,44.8 230.7,44.8 231.7,44.8 232.7,44.8 233.7,44.8 234.7,44.8 235.7,44.8 236.7,44.8 237.7,44.8 238.7,44.8 239.7,44.8 240.7,44.8 241.7,44.8 242.7,44.8 243.7,44.8 244.7,44.8 245.7,44.8 246.7,44.8 247.7,44.8 248.7,44.8 249.7,44.8 250.7,44.8 251.7,44.8 252.7,44.8 253.7,44.8 254.7,44.8 255.7,44.8 256.7,44.8 257.7,44.8 258.7,44.8 259.7,44.8 260.7,44.8 261.7,44.8 262.7,44.8 263.7,44.8 264.7,44.8 265.7,44.8 266.7,44.8 267.7,44.8 268.7,44.8 269.7,44.8 270.7,44.8 271.7,44.8 272.7,44.8 273.7,44.8 274.7,44.8 275.7,44.8 276.7,44.8 277.7,44.8 278.7,44.8 279.7,44.8 280.7,44.8 281.7,44.8 282.7,44.8 283.7,44.8 284.7,44.8 285.7,44.8 286.7,44.8 287.7,44.8 288.7,44.8 289.7,44.8 290.7,44.8 291.7,44.8 292.7,44.8 293.7,44.8 294.7,44.8 295.7,44.8 296.7,44.8 297.7,44.8 298.7,44.8 299.7,44.8 300.7,44.8 301.7,44.8 302.7,44.8 303.7,44.8 304.7,44.8 305.7,44.8 306.7,44.8 307.7,44.8 308.7,44.8 309.7,44.8 310.7,44.8 311.7,44.8 312.7,44.8 313.7,44.8 314.7,44.8 315.7,44.8 316.7,44.8 317.7,44.8 318.7,44.8 319.7,44.8 320.7,44.8 321.7,44.8 322.7,44.8 323.7,44.8 324.7,44.8 325.7,44.8 326.7,44.8 327.7,44.8 332.2,44.8 333.2,44.8 364.2,44.8 365.2,44.8 381.2,44.8 461.075,44.8 462.2,44.8 415.2,45.05 416.2,45.05 417.2,45.05 418.2,45.05 419.2,45.05 420.2,45.05 421.2,45.05 422.2,45.05 423.2,45.05 424.2,45.05 425.2,45.05 426.2,45.05 427.2,45.05 428.2,45.05 432.45,45.175 433.45,45.175 434.45,45.175 435.45,45.175 436.45,45.175 437.45,45.175 438.45,45.175 439.45,45.175 440.45,45.175 441.45,45.175 442.45,45.175 443.45,45.175 444.45,45.175 445.45,45.175 446.45,45.175 122.2,45.3 124.2,45.3 133.2,45.3 162.7,45.3 335.2,45.3 379.2,45.3 392.2,45.3 399.2,45.3 406.7,45.3 407.7,45.3 408.7,45.3 409.7,45.3 174.786,45.386 37.321,45.421 108.45,45.55 6.7,45.8 11.7,45.8 16.7,45.8 24.7,45.8 131.2,45.8 160.7,45.8 331.2,45.8 333.2,45.8 381.2,45.8 175.493,46.093 38.028,46.128 378.786,46.214 163.164,46.264 108.95,46.3 122.2,46.3 124.2,46.3 133.2,46.3 335.2,46.3 392.2,46.3 399.2,46.3 410.2,46.3 430.2,46.55 39.2,46.8 40.2,46.8 41.2,46.8 42.2,46.8 43.2,46.8 44.2,46.8 45.2,46.8 46.2,46.8 47.2,46.8 48.2,46.8 49.2,46.8 50.2,46.8 51.2,46.8 52.2,46.8 53.2,46.8 54.2,46.8 55.2,46.8 56.2,46.8 57.2,46.8 58.2,46.8 59.2,46.8 60.2,46.8 61.2,46.8 62.2,46.8 63.2,46.8 64.2,46.8 65.2,46.8 66.2,46.8 67.2,46.8 68.2,46.8 69.2,46.8 70.2,46.8 71.2,46.8 72.2,46.8 73.2,46.8 74.2,46.8 75.2,46.8 76.2,46.8 77.2,46.8 78.2,46.8 79.2,46.8 80.2,46.8 81.2,46.8 82.2,46.8 83.2,46.8 84.2,46.8 85.2,46.8 86.2,46.8 87.2,46.8 88.2,46.8 89.2,46.8 90.2,46.8 91.2,46.8 92.2,46.8 93.2,46.8 94.2,46.8 95.2,46.8 96.2,46.8 97.2,46.8 98.2,46.8 99.2,46.8 100.2,46.8 101.2,46.8 102.2,46.8 103.2,46.8 104.2,46.8 105.2,46.8 106.2,46.8 131.2,46.8 176.2,46.8 177.2,46.8 178.2,46.8 179.2,46.8 182.7,46.8 183.7,46.8 184.7,46.8 185.7,46.8 186.7,46.8 187.7,46.8 188.7,46.8 189.7,46.8 190.7,46.8 191.7,46.8 192.7,46.8 193.7,46.8 194.7,46.8 195.7,46.8 196.7,46.8 197.7,46.8 198.7,46.8 199.7,46.8 200.7,46.8 201.7,46.8 202.7,46.8 203.7,46.8 204.7,46.8 205.7,46.8 206.7,46.8 207.7,46.8 208.7,46.8 209.7,46.8 210.7,46.8 211.7,46.8 212.7,46.8 213.7,46.8 214.7,46.8 215.7,46.8 216.7,46.8 217.7,46.8 218.7,46.8 219.7,46.8 220.7,46.8 221.7,46.8 222.7,46.8 223.7,46.8 224.7,46.8 225.7,46.8 226.7,46.8 227.7,46.8 228.7,46.8 229.7,46.8 230.7,46.8 231.7,46.8 232.7,46.8 233.7,46.8 234.7,46.8 235.7,46.8 236.7,46.8 237.7,46.8 238.7,46.8 239.7,46.8 240.7,46.8 241.7,46.8 242.7,46.8 243.7,46.8 244.7,46.8 245.7,46.8 246.7,46.8 247.7,46.8 248.7,46.8 249.7,46.8 250.7,46.8 251.7,46.8 252.7,46.8 253.7,46.8 254.7,46.8 255.7,46.8 256.7,46.8 257.7,46.8 258.7,46.8 259.7,46.8 260.7,46.8 261.7,46.8 262.7,46.8 263.7,46.8 264.7,46.8 265.7,46.8 266.7,46.8 267.7,46.8 268.7,46.8 269.7,46.8 270.7,46.8 271.7,46.8 272.7,46.8 273.7,46.8 274.7,46.8 275.7,46.8 276.7,46.8 277.7,46.8 278.7,46.8 279.7,46.8 280.7,46.8 281.7,46.8 282.7,46.8 283.7,46.8 284.7,46.8 285.7,46.8 286.7,46.8 287.7,46.8 288.7,46.8 289.7,46.8 290.7,46.8 291.7,46.8 292.7,46.8 293.7,46.8 294.7,46.8 295.7,46.8 296.7,46.8 297.7,46.8 298.7,46.8 299.7,46.8 300.7,46.8 301.7,46.8 302.7,46.8 303.7,46.8 304.7,46.8 305.7,46.8 306.7,46.8 307.7,46.8 308.7,46.8 309.7,46.8 310.7,46.8 311.7,46.8 312.7,46.8 313.7,46.8 314.7,46.8 315.7,46.8 316.7,46.8 317.7,46.8 318.7,46.8 319.7,46.8 320.7,46.8 321.7,46.8 322.7,46.8 323.7,46.8 324.7,46.8 325.7,46.8 326.7,46.8 327.7,46.8 328.7,46.8 329.7,46.8 330.7,46.8 331.7,46.8 332.7,46.8 381.2,46.8 415.2,46.8 416.2,46.8 417.2,46.8 418.2,46.8 419.2,46.8 420.2,46.8 421.2,46.8 422.2,46.8 423.2,46.8 424.2,46.8 425.2,46.8 426.2,46.8 427.2,46.8 428.2,46.8 429.2,46.8 160.75,46.85 378.079,46.921 163.872,46.972 443.45,47.05 444.45,47.05 445.45,47.05 446.45,47.05 447.45,47.05 448.45,47.05 449.45,47.05 450.45,47.05 451.45,47.05 452.45,47.05 453.45,47.05 109.2,47.3 122.2,47.3 124.2,47.3 133.2,47.3 180.2,47.3 335.2,47.3 392.2,47.3 395.2,47.3 398.2,47.3 399.2,47.3 410.2,47.3 412.2,47.3 413.2,47.3 414.2,47.3 161.457,47.557 380.443,47.557 377.372,47.628 164.579,47.679 106.2,47.8 131.2,47.8 453.575,48.175 162.164,48.264 379.736,48.264 107.2,48.3 109.2,48.3 122.2,48.3 124.2,48.3 133.2,48.3 181.2,48.3 334.7,48.3 392.2,48.3 399.2,48.3 410.2,48.3 412.2,48.3 376.664,48.336 165.286,48.386 131.2,48.8 333.7,48.8 385.7,48.8 386.7,48.8 162.872,48.972 379.028,48.972 375.957,49.043 165.993,49.093 21.7,49.3 107.2,49.3 109.2,49.3 122.2,49.3 124.2,49.3 133.2,49.3 392.2,49.3 399.2,49.3 410.2,49.3 412.2,49.3 430.575,49.3 431.825,49.3 432.95,49.3 453.575,49.3 434.2,49.425 163.579,49.679 378.321,49.679 131.2,49.8 166.7,49.8 167.7,49.8 168.7,49.8 169.7,49.8 170.7,49.8 171.7,49.8 172.7,49.8 173.7,49.8 174.7,49.8 175.7,49.8 176.7,49.8 177.7,49.8 178.7,49.8 179.7,49.8 180.7,49.8 181.7,49.8 182.7,49.8 183.7,49.8 184.7,49.8 185.7,49.8 186.7,49.8 187.7,49.8 188.7,49.8 189.7,49.8 190.7,49.8 191.7,49.8 192.7,49.8 193.2,49.8 194.2,49.8 195.2,49.8 196.2,49.8 197.2,49.8 198.2,49.8 199.2,49.8 200.2,49.8 201.2,49.8 202.2,49.8 203.2,49.8 204.2,49.8 205.2,49.8 206.2,49.8 207.2,49.8 208.2,49.8 209.2,49.8 210.2,49.8 211.2,49.8 212.2,49.8 213.2,49.8 214.2,49.8 215.2,49.8 216.2,49.8 217.2,49.8 218.2,49.8 219.2,49.8 220.2,49.8 221.2,49.8 222.2,49.8 223.2,49.8 224.2,49.8 225.2,49.8 226.2,49.8 227.2,49.8 228.2,49.8 229.2,49.8 230.2,49.8 231.2,49.8 232.2,49.8 233.2,49.8 234.2,49.8 235.2,49.8 236.2,49.8 237.2,49.8 238.2,49.8 239.2,49.8 240.2,49.8 241.2,49.8 242.2,49.8 243.2,49.8 244.2,49.8 245.2,49.8 246.2,49.8 247.2,49.8 248.2,49.8 249.2,49.8 250.2,49.8 251.2,49.8 252.2,49.8 253.2,49.8 254.2,49.8 255.2,49.8 256.2,49.8 257.2,49.8 258.2,49.8 259.2,49.8 260.2,49.8 261.2,49.8 262.2,49.8 263.2,49.8 264.2,49.8 265.2,49.8 266.2,49.8 267.2,49.8 268.2,49.8 269.2,49.8 270.2,49.8 271.2,49.8 272.2,49.8 273.2,49.8 274.2,49.8 275.2,49.8 276.2,49.8 277.2,49.8 278.2,49.8 279.2,49.8 280.2,49.8 281.2,49.8 282.2,49.8 283.2,49.8 284.2,49.8 285.2,49.8 286.2,49.8 287.2,49.8 288.2,49.8 289.2,49.8 290.2,49.8 291.2,49.8 292.2,49.8 293.2,49.8 294.2,49.8 295.2,49.8 296.2,49.8 297.2,49.8 298.2,49.8 299.2,49.8 300.2,49.8 301.2,49.8 302.2,49.8 303.2,49.8 304.2,49.8 305.2,49.8 306.2,49.8 307.2,49.8 308.2,49.8 309.2,49.8 310.2,49.8 311.2,49.8 312.2,49.8 313.2,49.8 314.2,49.8 315.2,49.8 316.2,49.8 317.2,49.8 318.2,49.8 319.2,49.8 320.2,49.8 321.2,49.8 322.2,49.8 323.2,49.8 324.2,49.8 325.2,49.8 326.2,49.8 327.2,49.8 328.2,49.8 329.2,49.8 330.2,49.8 331.2,49.8 332.2,49.8 333.2,49.8 334.2,49.8 335.2,49.8 336.2,49.8 337.2,49.8 344.7,49.8 345.7,49.8 349.2,49.8 352.7,49.8 356.2,49.8 357.2,49.8 360.2,49.8 361.2,49.8 364.2,49.8 365.2,49.8 366.2,49.8 367.2,49.8 368.2,49.8 369.2,49.8 370.2,49.8 371.2,49.8 372.2,49.8 373.2,49.8 374.2,49.8 375.2,49.8 27.2,50.3 28.2,50.3 29.2,50.3 30.2,50.3 31.2,50.3 32.2,50.3 33.2,50.3 34.2,50.3 35.2,50.3 36.2,50.3 37.2,50.3 38.2,50.3 39.2,50.3 40.2,50.3 41.2,50.3 42.2,50.3 43.2,50.3 44.2,50.3 45.2,50.3 46.2,50.3 47.2,50.3 48.2,50.3 49.2,50.3 50.2,50.3 51.2,50.3 52.2,50.3 53.2,50.3 54.2,50.3 55.2,50.3 56.2,50.3 57.2,50.3 58.2,50.3 59.2,50.3 60.2,50.3 61.2,50.3 62.2,50.3 63.2,50.3 72.2,50.3 73.2,50.3 74.2,50.3 75.2,50.3 76.2,50.3 77.2,50.3 78.2,50.3 79.2,50.3 80.2,50.3 81.2,50.3 82.2,50.3 83.2,50.3 84.2,50.3 85.2,50.3 86.2,50.3 87.2,50.3 88.2,50.3 89.2,50.3 90.2,50.3 91.2,50.3 92.2,50.3 93.2,50.3 94.2,50.3 95.2,50.3 96.2,50.3 97.2,50.3 98.2,50.3 99.2,50.3 100.2,50.3 101.2,50.3 102.2,50.3 103.2,50.3 104.2,50.3 105.2,50.3 106.2,50.3 107.2,50.3 109.2,50.3 110.2,50.3 111.2,50.3 112.2,50.3 122.2,50.3 124.2,50.3 133.2,50.3 390.2,50.3 391.2,50.3 392.2,50.3 393.2,50.3 394.2,50.3 395.2,50.3 396.2,50.3 397.2,50.3 398.2,50.3 399.2,50.3 400.2,50.3 401.2,50.3 402.2,50.3 403.2,50.3 404.2,50.3 405.2,50.3 406.2,50.3 407.2,50.3 408.2,50.3 409.2,50.3 410.2,50.3 412.2,50.3 413.2,50.3 414.2,50.3 415.2,50.3 416.2,50.3 417.2,50.3 418.2,50.3 419.2,50.3 420.2,50.3 421.2,50.3 422.2,50.3 423.2,50.3 424.2,50.3 425.2,50.3 426.2,50.3 427.2,50.3 428.2,50.3 429.2,50.3 430.2,50.3 164.286,50.386 377.614,50.386 434.2,50.425 113.2,50.55 442.7,50.55 443.7,50.55 444.7,50.55 445.7,50.55 446.7,50.55 447.7,50.55 448.7,50.55 449.7,50.55 453.575,50.55 131.2,50.8 71.064,50.936 164.993,51.093 376.907,51.093 26.2,51.3 63.7,51.3 113.7,51.3 122.2,51.3 124.2,51.3 133.2,51.3 382.7,51.3 400.7,51.3 412.2,51.3 421.2,51.3 434.2,51.425 435.2,51.425 461.2,51.55 462.325,51.55 70.357,51.643 131.2,51.8 165.7,51.8 166.7,51.8 167.7,51.8 168.7,51.8 169.7,51.8 170.7,51.8 171.7,51.8 172.7,51.8 173.7,51.8 174.7,51.8 175.7,51.8 176.7,51.8 177.7,51.8 178.7,51.8 179.7,51.8 180.7,51.8 181.7,51.8 182.7,51.8 183.7,51.8 184.7,51.8 185.7,51.8 186.7,51.8 187.7,51.8 188.7,51.8 189.7,51.8 190.7,51.8 191.7,51.8 192.7,51.8 193.7,51.8 194.7,51.8 195.7,51.8 196.7,51.8 197.7,51.8 198.7,51.8 199.7,51.8 200.7,51.8 201.7,51.8 202.7,51.8 203.7,51.8 204.7,51.8 205.7,51.8 206.7,51.8 207.7,51.8 208.7,51.8 209.7,51.8 210.7,51.8 211.7,51.8 212.7,51.8 213.7,51.8 214.7,51.8 215.7,51.8 216.7,51.8 217.7,51.8 218.7,51.8 219.7,51.8 220.7,51.8 221.7,51.8 222.7,51.8 223.7,51.8 224.7,51.8 225.7,51.8 226.7,51.8 227.7,51.8 228.7,51.8 229.7,51.8 230.7,51.8 231.7,51.8 232.7,51.8 233.7,51.8 234.7,51.8 235.7,51.8 236.7,51.8 237.7,51.8 238.7,51.8 239.7,51.8 240.7,51.8 241.7,51.8 242.7,51.8 243.7,51.8 244.7,51.8 245.7,51.8 246.7,51.8 247.7,51.8 248.7,51.8 249.7,51.8 250.7,51.8 251.7,51.8 252.7,51.8 253.7,51.8 254.7,51.8 255.7,51.8 256.7,51.8 257.7,51.8 258.7,51.8 259.7,51.8 260.7,51.8 261.7,51.8 262.7,51.8 263.7,51.8 264.7,51.8 265.7,51.8 266.7,51.8 267.7,51.8 268.7,51.8 269.7,51.8 270.7,51.8 271.7,51.8 272.7,51.8 273.7,51.8 274.7,51.8 275.7,51.8 276.7,51.8 277.7,51.8 278.7,51.8 279.7,51.8 280.7,51.8 281.7,51.8 282.7,51.8 283.7,51.8 284.7,51.8 285.7,51.8 286.7,51.8 287.7,51.8 288.7,51.8 289.7,51.8 290.7,51.8 291.7,51.8 292.7,51.8 293.7,51.8 294.7,51.8 295.7,51.8 296.7,51.8 297.7,51.8 298.7,51.8 299.7,51.8 300.7,51.8 301.7,51.8 302.7,51.8 303.7,51.8 304.7,51.8 305.7,51.8 306.7,51.8 307.7,51.8 308.7,51.8 309.7,51.8 310.7,51.8 311.7,51.8 312.7,51.8 313.7,51.8 314.7,51.8 315.7,51.8 316.7,51.8 317.7,51.8 318.7,51.8 319.7,51.8 320.7,51.8 321.7,51.8 322.7,51.8 323.7,51.8 324.7,51.8 325.7,51.8 326.7,51.8 327.7,51.8 328.7,51.8 329.7,51.8 330.7,51.8 331.7,51.8 332.7,51.8 333.7,51.8 334.7,51.8 335.7,51.8 336.7,51.8 337.7,51.8 344.7,51.8 345.7,51.8 349.2,51.8 352.7,51.8 356.2,51.8 357.2,51.8 360.2,51.8 361.2,51.8 364.2,51.8 365.2,51.8 366.2,51.8 367.2,51.8 368.2,51.8 369.2,51.8 370.2,51.8 371.2,51.8 372.2,51.8 373.2,51.8 374.2,51.8 375.2,51.8 376.2,51.8 453.7,51.8 25.493,52.007 114.45,52.05 28.2,52.3 29.2,52.3 30.2,52.3 31.2,52.3 32.2,52.3 33.2,52.3 34.2,52.3 35.2,52.3 36.2,52.3 37.2,52.3 38.2,52.3 39.2,52.3 40.2,52.3 41.2,52.3 42.2,52.3 43.2,52.3 44.2,52.3 45.2,52.3 46.2,52.3 47.2,52.3 48.2,52.3 49.2,52.3 50.2,52.3 51.2,52.3 52.2,52.3 53.2,52.3 54.2,52.3 55.2,52.3 56.2,52.3 57.2,52.3 58.2,52.3 59.2,52.3 60.2,52.3 61.2,52.3 64.2,52.3 73.2,52.3 74.2,52.3 75.2,52.3 76.2,52.3 77.2,52.3 78.2,52.3 79.2,52.3 80.2,52.3 81.2,52.3 82.2,52.3 83.2,52.3 84.2,52.3 85.2,52.3 86.2,52.3 87.2,52.3 88.2,52.3 89.2,52.3 90.2,52.3 91.2,52.3 92.2,52.3 93.2,52.3 94.2,52.3 95.2,52.3 96.2,52.3 97.2,52.3 98.2,52.3 99.2,52.3 100.2,52.3 101.2,52.3 102.2,52.3 103.2,52.3 104.2,52.3 105.2,52.3 106.2,52.3 109.45,52.3 110.45,52.3 111.45,52.3 122.2,52.3 133.2,52.3 382.7,52.3 400.7,52.3 412.2,52.3 421.2,52.3 69.65,52.35 24.786,52.714 108.7,52.8 112.2,52.8 115.2,52.8 124.2,52.8 131.2,52.8 72.064,52.936 453.7,52.925 68.943,53.057 426.45,53.05 427.45,53.05 6.7,53.3 11.7,53.3 16.7,53.3 27.2,53.3 37.7,53.3 38.7,53.3 39.7,53.3 40.7,53.3 41.7,53.3 42.7,53.3 43.7,53.3 44.7,53.3 45.7,53.3 46.7,53.3 47.7,53.3 48.7,53.3 49.7,53.3 50.7,53.3 51.7,53.3 52.7,53.3 53.7,53.3 54.7,53.3 55.7,53.3 56.7,53.3 57.7,53.3 58.7,53.3 59.7,53.3 60.7,53.3 64.2,53.3 74.7,53.3 75.7,53.3 76.7,53.3 77.7,53.3 78.7,53.3 79.7,53.3 80.7,53.3 81.7,53.3 82.7,53.3 83.7,53.3 84.7,53.3 85.7,53.3 86.7,53.3 87.7,53.3 88.7,53.3 89.7,53.3 90.7,53.3 91.7,53.3 92.7,53.3 93.7,53.3 94.7,53.3 95.7,53.3 96.7,53.3 97.7,53.3 98.7,53.3 99.7,53.3 100.7,53.3 101.7,53.3 102.7,53.3 103.7,53.3 104.7,53.3 122.2,53.3 133.7,53.3 390.2,53.3 391.2,53.3 392.2,53.3 393.2,53.3 394.2,53.3 395.2,53.3 396.2,53.3 397.2,53.3 398.2,53.3 399.2,53.3 400.2,53.3 401.2,53.3 402.2,53.3 404.2,53.3 405.2,53.3 406.2,53.3 407.2,53.3 408.2,53.3 409.2,53.3 410.2,53.3 412.2,53.3 415.2,53.3 416.2,53.3 417.2,53.3 418.2,53.3 419.2,53.3 420.2,53.3 421.2,53.3 422.45,53.3 423.45,53.3 424.45,53.3 425.45,53.3 429.45,53.3 430.45,53.3 434.2,53.3 435.2,53.3 24.079,53.421 107.95,53.55 112.95,53.55 115.95,53.55 428.45,53.55 71.357,53.643 36.321,53.679 68.236,53.764 403.236,53.764 73.7,53.8 124.2,53.8 134.7,53.8 135.7,53.8 136.7,53.8 137.7,53.8 138.7,53.8 139.7,53.8 140.7,53.8 141.7,53.8 142.7,53.8 143.7,53.8 144.7,53.8 145.7,53.8 146.7,53.8 147.7,53.8 148.7,53.8 149.7,53.8 150.7,53.8 151.7,53.8 152.7,53.8 153.7,53.8 154.7,53.8 155.7,53.8 156.7,53.8 157.7,53.8 158.7,53.8 159.7,53.8 160.7,53.8 161.7,53.8 162.7,53.8 163.7,53.8 164.7,53.8 165.7,53.8 166.7,53.8 167.7,53.8 168.7,53.8 169.7,53.8 170.7,53.8 171.7,53.8 172.7,53.8 173.7,53.8 174.7,53.8 175.7,53.8 176.7,53.8 177.7,53.8 178.7,53.8 179.7,53.8 180.7,53.8 181.7,53.8 182.7,53.8 183.7,53.8 184.7,53.8 185.7,53.8 186.7,53.8 187.7,53.8 188.7,53.8 189.7,53.8 190.7,53.8 191.7,53.8 192.7,53.8 193.7,53.8 194.7,53.8 195.7,53.8 196.7,53.8 197.7,53.8 198.7,53.8 199.7,53.8 200.7,53.8 201.7,53.8 202.7,53.8 203.7,53.8 204.7,53.8 205.7,53.8 206.7,53.8 207.7,53.8 208.7,53.8 209.7,53.8 210.7,53.8 211.7,53.8 212.7,53.8 213.7,53.8 214.7,53.8 215.7,53.8 216.7,53.8 217.7,53.8 218.7,53.8 219.7,53.8 220.7,53.8 221.7,53.8 222.7,53.8 223.7,53.8 224.7,53.8 225.7,53.8 226.7,53.8 227.7,53.8 228.7,53.8 229.7,53.8 230.7,53.8 231.7,53.8 232.7,53.8 233.7,53.8 234.7,53.8 235.7,53.8 236.7,53.8 237.7,53.8 238.7,53.8 239.7,53.8 240.7,53.8 241.7,53.8 242.7,53.8 243.7,53.8 244.7,53.8 245.7,53.8 246.7,53.8 247.7,53.8 248.7,53.8 249.7,53.8 250.7,53.8 251.7,53.8 252.7,53.8 253.7,53.8 254.7,53.8 255.7,53.8 256.7,53.8 257.7,53.8 258.7,53.8 259.7,53.8 260.7,53.8 261.7,53.8 262.7,53.8 263.7,53.8 264.7,53.8 265.7,53.8 266.7,53.8 267.7,53.8 268.7,53.8 269.7,53.8 270.7,53.8 271.7,53.8 272.7,53.8 273.7,53.8 274.7,53.8 275.7,53.8 276.7,53.8 277.7,53.8 278.7,53.8 279.7,53.8 280.7,53.8 281.7,53.8 282.7,53.8 283.7,53.8 284.7,53.8 285.7,53.8 286.7,53.8 287.7,53.8 288.7,53.8 289.7,53.8 290.7,53.8 291.7,53.8 292.7,53.8 293.7,53.8 294.7,53.8 295.7,53.8 296.7,53.8 297.7,53.8 298.7,53.8 299.7,53.8 300.7,53.8 301.7,53.8 302.7,53.8 303.7,53.8 304.7,53.8 305.7,53.8 306.7,53.8 307.7,53.8 308.7,53.8 309.7,53.8 310.7,53.8 311.7,53.8 312.7,53.8 313.7,53.8 314.7,53.8 315.7,53.8 316.7,53.8 317.7,53.8 318.7,53.8 319.7,53.8 320.7,53.8 321.7,53.8 322.7,53.8 323.7,53.8 324.7,53.8 325.7,53.8 326.7,53.8 327.7,53.8 328.7,53.8 329.7,53.8 330.7,53.8 331.7,53.8 332.7,53.8 333.7,53.8 334.7,53.8 335.7,53.8 336.7,53.8 337.7,53.8 344.7,53.8 345.7,53.8 349.2,53.8 352.7,53.8 356.2,53.8 357.2,53.8 360.2,53.8 361.2,53.8 364.2,53.8 365.2,53.8 366.2,53.8 367.2,53.8 368.2,53.8 369.2,53.8 370.2,53.8 371.2,53.8 372.2,53.8 373.2,53.8 374.2,53.8 375.2,53.8 376.2,53.8 454.7,53.8 455.825,53.8 457.075,53.8 131.236,53.836 377.372,53.972 26.493,54.007 435.95,54.05 436.95,54.05 437.95,54.05 439.075,54.05 440.075,54.05 441.075,54.05 442.075,54.05 443.075,54.05 444.075,54.05 445.075,54.05 446.075,54.05 447.075,54.05 448.075,54.05 449.075,54.05 23.372,54.128 63.7,54.3 107.2,54.3 113.7,54.3 116.7,54.3 122.2,54.3 412.2,54.3 415.2,54.3 430.2,54.3 431.95,54.3 433.7,54.3 434.7,54.3 465.075,54.3 70.65,54.35 35.614,54.386 67.528,54.472 402.528,54.472 131.943,54.543 378.079,54.679 25.786,54.714 62.7,54.8 73.2,54.8 124.2,54.8 22.664,54.836 449.825,54.925 114.45,55.05 117.45,55.05 69.943,55.057 34.907,55.093 66.821,55.179 401.821,55.179 132.65,55.25 37.7,55.3 38.7,55.3 39.7,55.3 40.7,55.3 41.7,55.3 42.7,55.3 43.7,55.3 44.7,55.3 45.7,55.3 46.7,55.3 47.7,55.3 48.7,55.3 49.7,55.3 50.7,55.3 51.7,55.3 52.7,55.3 53.7,55.3 54.7,55.3 55.7,55.3 56.7,55.3 57.7,55.3 58.7,55.3 59.7,55.3 60.7,55.3 61.7,55.3 75.7,55.3 76.7,55.3 77.7,55.3 78.7,55.3 79.7,55.3 80.7,55.3 81.7,55.3 82.7,55.3 83.7,55.3 84.7,55.3 85.7,55.3 86.7,55.3 87.7,55.3 88.7,55.3 89.7,55.3 90.7,55.3 91.7,55.3 92.7,55.3 93.7,55.3 94.7,55.3 95.7,55.3 96.7,55.3 97.7,55.3 98.7,55.3 99.7,55.3 100.7,55.3 101.7,55.3 102.7,55.3 103.7,55.3 104.7,55.3 105.7,55.3 106.7,55.3 122.2,55.3 385.7,55.3 386.7,55.3 412.2,55.3 415.2,55.3 430.2,55.3 435.2,55.3 378.786,55.386 25.079,55.421 465.075,55.425 21.957,55.543 69.236,55.764 73.2,55.8 115.2,55.8 118.2,55.8 124.2,55.8 133.7,55.8 134.7,55.8 135.7,55.8 136.7,55.8 137.7,55.8 138.7,55.8 139.7,55.8 140.7,55.8 141.7,55.8 142.7,55.8 143.7,55.8 144.7,55.8 145.7,55.8 146.7,55.8 147.7,55.8 148.7,55.8 149.7,55.8 150.7,55.8 151.7,55.8 152.7,55.8 153.7,55.8 154.7,55.8 155.7,55.8 156.7,55.8 157.7,55.8 158.7,55.8 159.7,55.8 160.7,55.8 161.7,55.8 162.7,55.8 163.7,55.8 164.7,55.8 165.7,55.8 166.7,55.8 167.7,55.8 168.7,55.8 169.7,55.8 170.7,55.8 171.7,55.8 172.7,55.8 173.7,55.8 174.7,55.8 175.7,55.8 176.7,55.8 177.7,55.8 178.7,55.8 179.7,55.8 180.7,55.8 181.7,55.8 182.7,55.8 183.7,55.8 184.7,55.8 185.7,55.8 186.7,55.8 187.7,55.8 188.7,55.8 189.7,55.8 190.7,55.8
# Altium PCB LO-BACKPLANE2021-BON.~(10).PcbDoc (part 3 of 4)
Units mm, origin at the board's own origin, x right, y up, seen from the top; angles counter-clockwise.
Board outline 469.9 x 101.6 mm, 4 copper layers (1, Signal Layer 1, Signal Layer 2, 4), stack 1.53 mm thick; 160 components, 92 nets, 524 pads, 8353 vias.

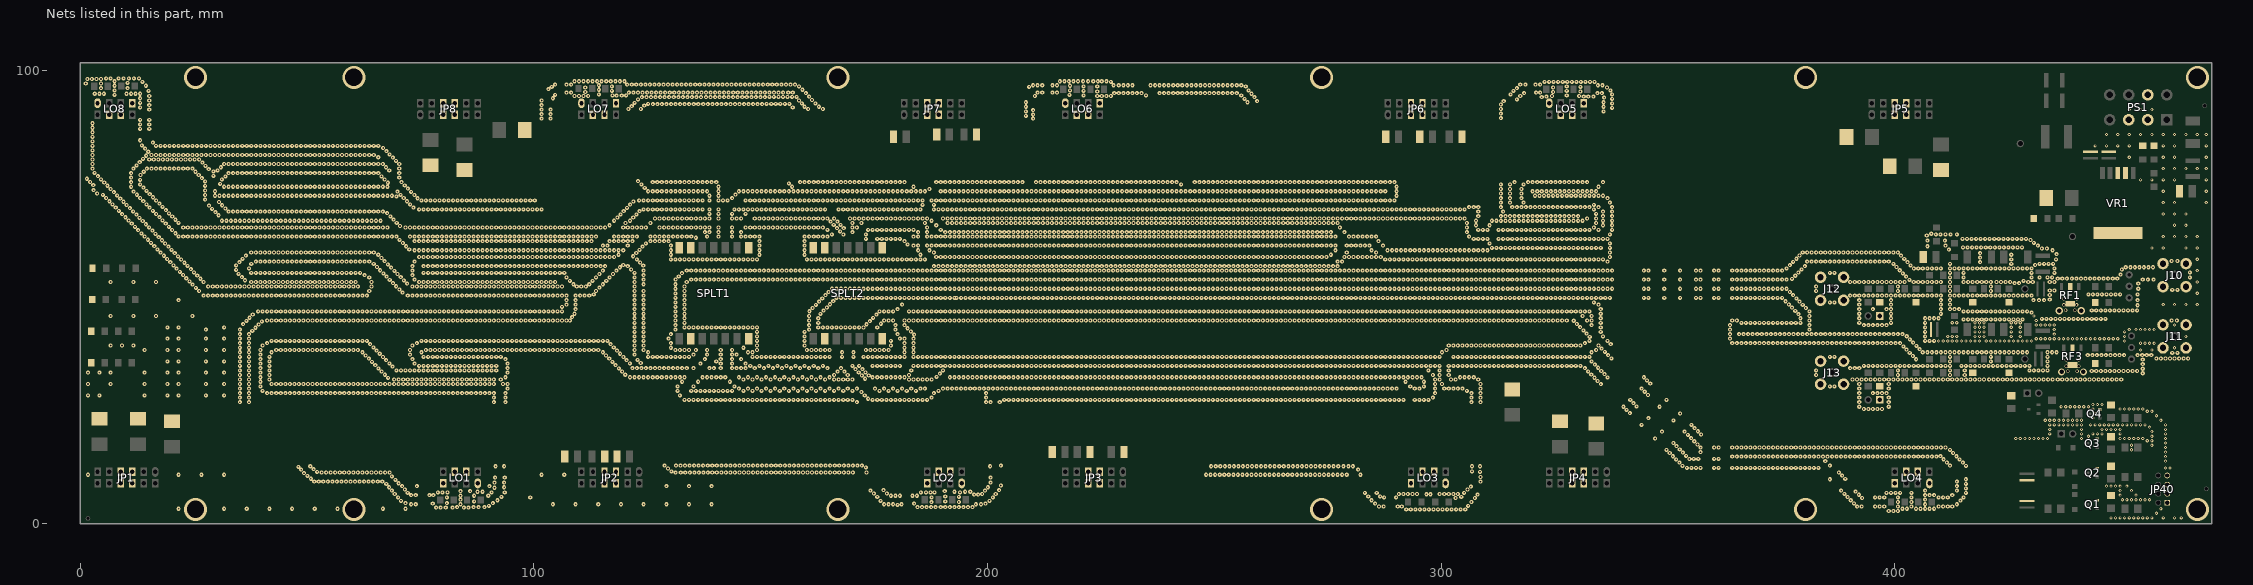
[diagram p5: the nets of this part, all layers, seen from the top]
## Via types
v1: diameter 0.9, hole 0.35, 1 to 4, 7972 vias
v2: diameter 0.7, hole 0.3, 1 to 4, 286 vias
v3: diameter 1.6, hole 1, 1 to 4, 60 vias
v4: diameter 0.762, hole 0.508, 1 to 4, 12 vias
v5: diameter 5.08, hole 3.85, 1 to 4, 12 vias
v6: diameter 2, hole 1.1, 1 to 4, 10 vias
v7: diameter 1.27, hole 0.7, 1 to 4, 1 vias

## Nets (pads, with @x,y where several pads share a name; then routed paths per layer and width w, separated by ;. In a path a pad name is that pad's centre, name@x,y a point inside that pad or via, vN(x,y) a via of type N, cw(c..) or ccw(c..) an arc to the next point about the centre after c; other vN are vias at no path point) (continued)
GND: (continued)
  other v1: 191.7,55.8 192.7,55.8 193.7,55.8 194.7,55.8 195.7,55.8 196.7,55.8 197.7,55.8 198.7,55.8 199.7,55.8 200.7,55.8 201.7,55.8 202.7,55.8 203.7,55.8 204.7,55.8 205.7,55.8 206.7,55.8 207.7,55.8 208.7,55.8 209.7,55.8 210.7,55.8 211.7,55.8 212.7,55.8 213.7,55.8 214.7,55.8 215.7,55.8 216.7,55.8 217.7,55.8 218.7,55.8 219.7,55.8 220.7,55.8 221.7,55.8 222.7,55.8 223.7,55.8 224.7,55.8 225.7,55.8 226.7,55.8 227.7,55.8 228.7,55.8 229.7,55.8 230.7,55.8 231.7,55.8 232.7,55.8 233.7,55.8 234.7,55.8 235.7,55.8 236.7,55.8 237.7,55.8 238.7,55.8 239.7,55.8 240.7,55.8 241.7,55.8 242.7,55.8 243.7,55.8 244.7,55.8 245.7,55.8 246.7,55.8 247.7,55.8 248.7,55.8 249.7,55.8 250.7,55.8 251.7,55.8 252.7,55.8 253.7,55.8 254.7,55.8 255.7,55.8 256.7,55.8 257.7,55.8 258.7,55.8 259.7,55.8 260.7,55.8 261.7,55.8 262.7,55.8 263.7,55.8 264.7,55.8 265.7,55.8 266.7,55.8 267.7,55.8 268.7,55.8 269.7,55.8 270.7,55.8 271.7,55.8 272.7,55.8 273.7,55.8 274.7,55.8 275.7,55.8 276.7,55.8 277.7,55.8 278.7,55.8 279.7,55.8 280.7,55.8 281.7,55.8 282.7,55.8 283.7,55.8 284.7,55.8 285.7,55.8 286.7,55.8 287.7,55.8 288.7,55.8 289.7,55.8 290.7,55.8 291.7,55.8 292.7,55.8 293.7,55.8 294.7,55.8 295.7,55.8 296.7,55.8 297.7,55.8 298.7,55.8 299.7,55.8 300.7,55.8 301.7,55.8 302.7,55.8 303.7,55.8 304.7,55.8 305.7,55.8 306.7,55.8 307.7,55.8 308.7,55.8 309.7,55.8 310.7,55.8 311.7,55.8 312.7,55.8 313.7,55.8 314.7,55.8 315.7,55.8 316.7,55.8 317.7,55.8 318.7,55.8 319.7,55.8 320.7,55.8 321.7,55.8 322.7,55.8 323.7,55.8 324.7,55.8 325.7,55.8 326.7,55.8 327.7,55.8 328.7,55.8 329.7,55.8 330.7,55.8 331.7,55.8 332.7,55.8 333.7,55.8 334.7,55.8 335.7,55.8 336.7,55.8 337.7,55.8 344.7,55.8 345.7,55.8 349.2,55.8 352.7,55.8 356.2,55.8 357.2,55.8 360.2,55.8 361.2,55.8 364.2,55.8 365.2,55.8 366.2,55.8 367.2,55.8 368.2,55.8 369.2,55.8 370.2,55.8 371.2,55.8 372.2,55.8 373.2,55.8 374.2,55.8 375.2,55.8 66.114,55.886 401.114,55.886 34.372,55.972 121.45,56.05 450.075,56.05 379.493,56.093 24.372,56.128 21.25,56.25 404.236,56.264 37.2,56.3 376.2,56.3 405.2,56.3 406.2,56.3 407.2,56.3 408.2,56.3 409.2,56.3 410.2,56.3 412.2,56.3 413.2,56.3 414.2,56.3 415.2,56.3 416.2,56.3 417.2,56.3 418.2,56.3 419.2,56.3 420.2,56.3 421.2,56.3 422.2,56.3 423.2,56.3 424.2,56.3 425.2,56.3 426.2,56.3 427.2,56.3 428.2,56.3 429.2,56.3 430.2,56.3 435.2,56.3 68.528,56.472 118.95,56.55 450.95,56.55 451.95,56.55 452.95,56.55 453.95,56.55 454.95,56.55 455.95,56.55 456.95,56.55 65.407,56.593 400.407,56.593 73.2,56.8 75.7,56.8 76.7,56.8 77.7,56.8 78.7,56.8 79.7,56.8 80.7,56.8 81.7,56.8 82.7,56.8 83.7,56.8 84.7,56.8 85.7,56.8 86.7,56.8 87.7,56.8 88.7,56.8 89.7,56.8 90.7,56.8 91.7,56.8 92.7,56.8 93.7,56.8 94.7,56.8 95.7,56.8 96.7,56.8 97.7,56.8 98.7,56.8 99.7,56.8 100.7,56.8 101.7,56.8 102.7,56.8 103.7,56.8 104.7,56.8 105.7,56.8 106.7,56.8 107.7,56.8 108.7,56.8 109.7,56.8 110.7,56.8 111.7,56.8 112.7,56.8 113.7,56.8 114.7,56.8 115.7,56.8 120.7,56.8 188.2,56.8 189.2,56.8 190.2,56.8 191.2,56.8 192.2,56.8 193.2,56.8 194.2,56.8 195.2,56.8 196.2,56.8 197.2,56.8 198.2,56.8 199.2,56.8 200.2,56.8 201.2,56.8 202.2,56.8 203.2,56.8 204.2,56.8 205.2,56.8 206.2,56.8 207.2,56.8 208.2,56.8 209.2,56.8 210.2,56.8 211.2,56.8 212.2,56.8 213.2,56.8 214.2,56.8 215.2,56.8 216.2,56.8 217.2,56.8 218.2,56.8 219.2,56.8 220.2,56.8 221.2,56.8 222.2,56.8 223.2,56.8 224.2,56.8 225.2,56.8 226.2,56.8 227.2,56.8 228.2,56.8 229.2,56.8 230.2,56.8 231.2,56.8 232.2,56.8 233.2,56.8 234.2,56.8 235.2,56.8 236.2,56.8 237.2,56.8 238.2,56.8 239.2,56.8 240.2,56.8 241.2,56.8 242.2,56.8 243.2,56.8 244.2,56.8 245.2,56.8 246.2,56.8 247.2,56.8 248.2,56.8 249.2,56.8 250.2,56.8 251.2,56.8 252.2,56.8 253.2,56.8 254.2,56.8 255.2,56.8 256.2,56.8 257.2,56.8 258.2,56.8 259.2,56.8 260.2,56.8 261.2,56.8 262.2,56.8 263.2,56.8 264.2,56.8 265.2,56.8 266.2,56.8 267.2,56.8 268.2,56.8 269.2,56.8 270.2,56.8 271.2,56.8 272.2,56.8 273.2,56.8 274.2,56.8 275.2,56.8 276.2,56.8 277.2,56.8 380.2,56.8 23.664,56.836 124.114,56.886 20.543,56.957 34.372,56.972 403.528,56.972 376.907,57.007 119.7,57.05 430.95,57.05 67.821,57.179 37.7,57.3 64.7,57.3 399.7,57.3 412.2,57.3 425.7,57.3 431.95,57.3 432.95,57.3 433.95,57.3 434.95,57.3 22.957,57.543 123.407,57.593 19.836,57.664 35.079,57.679 402.821,57.679 418.825,57.675 377.614,57.714 38.7,57.8 39.7,57.8 40.7,57.8 41.7,57.8 42.7,57.8 43.7,57.8 44.7,57.8 45.7,57.8 46.7,57.8 47.7,57.8 48.7,57.8 49.7,57.8 50.7,57.8 51.7,57.8 52.7,57.8 53.7,57.8 54.7,57.8 55.7,57.8 56.7,57.8 57.7,57.8 58.7,57.8 59.7,57.8 60.7,57.8 61.7,57.8 62.7,57.8 63.7,57.8 73.7,57.8 277.2,57.8 278.2,57.8 336.7,57.8 380.7,57.8 381.7,57.8 382.7,57.8 383.7,57.8 384.7,57.8 385.7,57.8 386.7,57.8 387.7,57.8 388.7,57.8 389.7,57.8 390.7,57.8 391.7,57.8 392.7,57.8 393.7,57.8 394.7,57.8 395.7,57.8 396.7,57.8 397.7,57.8 398.7,57.8 67.114,57.886 461.075,57.925 462.325,57.925 22.25,58.25 122.7,58.3 130.2,58.3 131.2,58.3 132.2,58.3 133.2,58.3 134.2,58.3 135.2,58.3 136.2,58.3 137.2,58.3 138.2,58.3 139.2,58.3 140.2,58.3 141.2,58.3 142.2,58.3 143.2,58.3 144.2,58.3 145.2,58.3 146.2,58.3 147.2,58.3 148.2,58.3 149.2,58.3 160.2,58.3 161.2,58.3 162.2,58.3 163.2,58.3 164.2,58.3 165.2,58.3 166.2,58.3 167.2,58.3 168.2,58.3 169.2,58.3 170.2,58.3 171.2,58.3 172.2,58.3 173.2,58.3 174.2,58.3 175.2,58.3 176.2,58.3 177.2,58.3 178.2,58.3 179.2,58.3 180.2,58.3 181.2,58.3 182.2,58.3 183.2,58.3 184.2,58.3 185.2,58.3 186.2,58.3 287.7,58.3 288.7,58.3 289.7,58.3 290.7,58.3 291.7,58.3 292.7,58.3 293.7,58.3 294.7,58.3 295.7,58.3 296.7,58.3 297.7,58.3 298.7,58.3 299.7,58.3 300.7,58.3 301.7,58.3 302.7,58.3 303.7,58.3 304.7,58.3 305.7,58.3 306.7,58.3 307.7,58.3 308.7,58.3 309.7,58.3 310.7,58.3 311.7,58.3 312.7,58.3 313.7,58.3 314.7,58.3 315.7,58.3 316.7,58.3 317.7,58.3 318.7,58.3 319.7,58.3 320.7,58.3 321.7,58.3 322.7,58.3 323.7,58.3 324.7,58.3 325.7,58.3 326.7,58.3 327.7,58.3 328.7,58.3 329.7,58.3 330.7,58.3 331.7,58.3 332.7,58.3 333.7,58.3 334.7,58.3 335.7,58.3 425.7,58.3 435.575,58.3 19.129,58.371 35.786,58.386 402.114,58.386 378.321,58.421 66.407,58.593 418.825,58.675 74.7,58.8 75.7,58.8 76.7,58.8 77.7,58.8 78.7,58.8 79.7,58.8 80.7,58.8 81.7,58.8 82.7,58.8 83.7,58.8 84.7,58.8 85.7,58.8 86.7,58.8 87.7,58.8 88.7,58.8 89.7,58.8 90.7,58.8 91.7,58.8 92.7,58.8 93.7,58.8 94.7,58.8 95.7,58.8 96.7,58.8 97.7,58.8 98.7,58.8 99.7,58.8 100.7,58.8 101.7,58.8 102.7,58.8 103.7,58.8 104.7,58.8 105.7,58.8 106.7,58.8 107.7,58.8 108.7,58.8 109.7,58.8 110.7,58.8 111.7,58.8 112.7,58.8 113.7,58.8 114.7,58.8 115.7,58.8 116.7,58.8 117.7,58.8 188.7,58.8 189.7,58.8 190.7,58.8 191.7,58.8 192.7,58.8 193.7,58.8 194.7,58.8 195.7,58.8 196.7,58.8 197.7,58.8 198.7,58.8 199.7,58.8 200.7,58.8 201.7,58.8 202.7,58.8 203.7,58.8 204.7,58.8 205.7,58.8 206.7,58.8 207.7,58.8 208.7,58.8 209.7,58.8 210.7,58.8 211.7,58.8 212.7,58.8 213.7,58.8 214.7,58.8 215.7,58.8 216.7,58.8 217.7,58.8 218.7,58.8 219.7,58.8 220.7,58.8 221.7,58.8 222.7,58.8 223.7,58.8 224.7,58.8 225.7,58.8 226.7,58.8 227.7,58.8 228.7,58.8 229.7,58.8 230.7,58.8 231.7,58.8 232.7,58.8 233.7,58.8 234.7,58.8 235.7,58.8 236.7,58.8 237.7,58.8 238.7,58.8 239.7,58.8 240.7,58.8 241.7,58.8 242.7,58.8 243.7,58.8 244.7,58.8 245.7,58.8 246.7,58.8 247.7,58.8 248.7,58.8 249.7,58.8 250.7,58.8 251.7,58.8 252.7,58.8 253.7,58.8 254.7,58.8 255.7,58.8 256.7,58.8 257.7,58.8 258.7,58.8 259.7,58.8 260.7,58.8 261.7,58.8 262.7,58.8 263.7,58.8 264.7,58.8 265.7,58.8 266.7,58.8 267.7,58.8 268.7,58.8 269.7,58.8 270.7,58.8 271.7,58.8 272.7,58.8 273.7,58.8 274.7,58.8 278.7,58.8 279.7,58.8 280.7,58.8 281.7,58.8 282.7,58.8 283.7,58.8 284.7,58.8 285.7,58.8 286.7,58.8 337.2,58.8 21.543,58.957 121.872,58.972 18.422,59.078 36.493,59.093 401.407,59.093 379.028,59.128 65.7,59.3 118.7,59.3 130.2,59.3 149.7,59.3 159.7,59.3 185.2,59.3 275.7,59.3 425.7,59.3 435.7,59.425 20.836,59.664 418.825,59.675 122.579,59.679 17.715,59.785 37.7,59.8 38.7,59.8 39.7,59.8 40.7,59.8 41.7,59.8 42.7,59.8 43.7,59.8 44.7,59.8 45.7,59.8 46.7,59.8 47.7,59.8 48.7,59.8 49.7,59.8 50.7,59.8 51.7,59.8 52.7,59.8 53.7,59.8 54.7,59.8 55.7,59.8 56.7,59.8 57.7,59.8 58.7,59.8 59.7,59.8 60.7,59.8 61.7,59.8 62.7,59.8 63.7,59.8 64.7,59.8 188.2,59.8 279.2,59.8 285.7,59.8 337.2,59.8 380.7,59.8 381.7,59.8 382.7,59.8 383.7,59.8 384.7,59.8 385.7,59.8 386.7,59.8 387.7,59.8 388.7,59.8 389.7,59.8 390.7,59.8 391.7,59.8 392.7,59.8 393.7,59.8 394.7,59.8 395.7,59.8 396.7,59.8 397.7,59.8 398.7,59.8 399.7,59.8 400.7,59.8 379.736,59.836 73.7,60.3 74.7,60.3 75.7,60.3 76.7,60.3 77.7,60.3 78.7,60.3 79.7,60.3 80.7,60.3 81.7,60.3 82.7,60.3 83.7,60.3 84.7,60.3 85.7,60.3 86.7,60.3 87.7,60.3 88.7,60.3 89.7,60.3 90.7,60.3 91.7,60.3 92.7,60.3 93.7,60.3 94.7,60.3 95.7,60.3 96.7,60.3 97.7,60.3 98.7,60.3 99.7,60.3 100.7,60.3 101.7,60.3 102.7,60.3 103.7,60.3 104.7,60.3 105.7,60.3 106.7,60.3 107.7,60.3 108.7,60.3 109.7,60.3 110.7,60.3 111.7,60.3 112.7,60.3 113.7,60.3 114.7,60.3 115.7,60.3 116.7,60.3 117.7,60.3 118.7,60.3 119.7,60.3 130.2,60.3 149.7,60.3 159.7,60.3 184.7,60.3 187.2,60.3 276.7,60.3 284.7,60.3 288.2,60.3 289.2,60.3 290.2,60.3 291.2,60.3 292.2,60.3 293.2,60.3 294.2,60.3 295.2,60.3 296.2,60.3 297.2,60.3 298.2,60.3 299.2,60.3 300.2,60.3 301.2,60.3 302.2,60.3 303.2,60.3 304.2,60.3 305.2,60.3 306.2,60.3 307.2,60.3 308.2,60.3 309.2,60.3 310.2,60.3 434.825,60.3 20.129,60.371 123.286,60.386 411.95,60.425 72.528,60.472 17.008,60.492 432.45,60.675 433.575,60.675 311.2,60.8 312.2,60.8 313.2,60.8 314.2,60.8 315.2,60.8 316.2,60.8 317.2,60.8 318.2,60.8 319.2,60.8 320.2,60.8 321.2,60.8 322.2,60.8 323.2,60.8 324.2,60.8 325.2,60.8 326.2,60.8 327.2,60.8 328.2,60.8 329.2,60.8 330.2,60.8 331.2,60.8 332.2,60.8 333.2,60.8 334.2,60.8 335.2,60.8 337.2,60.8 415.075,60.925 416.075,60.925 417.075,60.925 418.075,60.925 419.075,60.925 420.075,60.925 421.075,60.925 422.075,60.925 423.075,60.925 424.075,60.925 425.075,60.925 426.075,60.925 427.075,60.925 428.075,60.925 19.422,61.078 123.993,61.093 407.2,61.175 16.301,61.199 71.821,61.179 115.2,61.3 116.2,61.3 120.7,61.3 130.2,61.3 149.7,61.3 159.7,61.3 183.7,61.3 184.7,61.3 186.7,61.3 187.7,61.3 188.7,61.3 189.7,61.3 190.7,61.3 191.7,61.3 192.7,61.3 193.7,61.3 194.7,61.3 195.7,61.3 196.7,61.3 197.7,61.3 198.7,61.3 199.7,61.3 200.7,61.3 201.7,61.3 202.7,61.3 203.7,61.3 204.7,61.3 205.7,61.3 206.7,61.3 207.7,61.3 208.7,61.3 209.7,61.3 210.7,61.3 211.7,61.3 212.7,61.3 213.7,61.3 214.7,61.3 215.7,61.3 216.7,61.3 217.7,61.3 218.7,61.3 219.7,61.3 220.7,61.3 221.7,61.3 222.7,61.3 223.7,61.3 224.7,61.3 225.7,61.3 226.7,61.3 227.7,61.3 228.7,61.3 229.7,61.3 230.7,61.3 231.7,61.3 232.7,61.3 233.7,61.3 234.7,61.3 235.7,61.3 236.7,61.3 237.7,61.3 238.7,61.3 239.7,61.3 240.7,61.3 241.7,61.3 242.7,61.3 243.7,61.3 244.7,61.3 245.7,61.3 246.7,61.3 247.7,61.3 248.7,61.3 249.7,61.3 250.7,61.3 251.7,61.3 252.7,61.3 253.7,61.3 254.7,61.3 255.7,61.3 256.7,61.3 257.7,61.3 258.7,61.3 259.7,61.3 260.7,61.3 261.7,61.3 262.7,61.3 263.7,61.3 264.7,61.3 265.7,61.3 266.7,61.3 267.7,61.3 268.7,61.3 269.7,61.3 270.7,61.3 271.7,61.3 272.7,61.3 273.7,61.3 274.7,61.3 275.7,61.3 276.7,61.3 279.2,61.3 280.2,61.3 281.2,61.3 282.2,61.3 283.2,61.3 284.2,61.3 287.2,61.3 411.2,61.3 431.575,61.3 182.407,61.593 18.715,61.785 124.7,61.8 310.7,61.8 337.2,61.8 71.114,61.886 15.593,61.907 430.7,61.925 73.7,62.3 74.7,62.3 75.7,62.3 76.7,62.3 77.7,62.3 78.7,62.3 79.7,62.3 80.7,62.3 81.7,62.3 82.7,62.3 83.7,62.3 84.7,62.3 85.7,62.3 86.7,62.3 87.7,62.3 88.7,62.3 89.7,62.3 90.7,62.3 91.7,62.3 92.7,62.3 93.7,62.3 94.7,62.3 95.7,62.3 96.7,62.3 97.7,62.3 98.7,62.3 99.7,62.3 100.7,62.3 101.7,62.3 102.7,62.3 103.7,62.3 104.7,62.3 105.7,62.3 106.7,62.3 107.7,62.3 108.7,62.3 109.7,62.3 110.7,62.3 111.7,62.3 112.7,62.3 116.7,62.3 117.7,62.3 118.7,62.3 119.7,62.3 120.7,62.3 121.7,62.3 125.7,62.3 126.7,62.3 127.7,62.3 128.7,62.3 129.7,62.3 149.7,62.3 159.7,62.3 181.7,62.3 286.2,62.3 407.2,62.425 411.075,62.425 18.008,62.492 429.95,62.55 70.407,62.593 14.886,62.614 173.2,62.8 175.7,62.8 176.7,62.8 177.7,62.8 178.7,62.8 179.7,62.8 180.7,62.8 307.2,62.8 308.2,62.8 309.2,62.8 310.2,62.8 312.7,62.8 313.7,62.8 314.7,62.8 315.7,62.8 316.7,62.8 317.7,62.8 318.7,62.8 319.7,62.8 320.7,62.8 321.7,62.8 322.7,62.8 323.7,62.8 324.7,62.8 325.7,62.8 326.7,62.8 327.7,62.8 328.7,62.8 329.7,62.8 330.7,62.8 331.7,62.8 332.7,62.8 333.7,62.8 334.7,62.8 335.7,62.8 336.7,62.8 414.95,62.8 415.95,62.8 416.95,62.8 417.95,62.8 418.95,62.8 419.95,62.8 420.95,62.8 421.95,62.8 422.95,62.8 423.95,62.8 424.95,62.8 425.95,62.8 426.95,62.8 427.95,62.8 428.95,62.8 135.7,63.05 17.301,63.199 22.7,63.3 23.7,63.3 24.7,63.3 25.7,63.3 26.7,63.3 27.7,63.3 28.7,63.3 29.7,63.3 30.7,63.3 31.7,63.3 32.7,63.3 33.7,63.3 34.7,63.3 35.7,63.3 36.7,63.3 37.7,63.3 38.7,63.3 39.7,63.3 40.7,63.3 41.7,63.3 42.7,63.3 43.7,63.3 44.7,63.3 45.7,63.3 46.7,63.3 47.7,63.3 48.7,63.3 49.7,63.3 50.7,63.3 51.7,63.3 52.7,63.3 53.7,63.3 54.7,63.3 55.7,63.3 56.7,63.3 57.7,63.3 58.7,63.3 59.7,63.3 60.7,63.3 61.7,63.3 62.7,63.3 63.7,63.3 64.7,63.3 65.7,63.3 66.7,63.3 67.7,63.3 68.7,63.3 69.7,63.3 72.7,63.3 73.7,63.3 74.7,63.3 75.7,63.3 76.7,63.3 77.7,63.3 78.7,63.3 79.7,63.3 80.7,63.3 81.7,63.3 82.7,63.3 83.7,63.3 84.7,63.3 85.7,63.3 86.7,63.3 87.7,63.3 88.7,63.3 89.7,63.3 90.7,63.3 91.7,63.3 92.7,63.3 93.7,63.3 94.7,63.3 95.7,63.3 96.7,63.3 97.7,63.3 98.7,63.3 99.7,63.3 100.7,63.3 101.7,63.3 102.7,63.3 103.7,63.3 104.7,63.3 105.7,63.3 106.7,63.3 107.7,63.3 108.7,63.3 109.7,63.3 110.7,63.3 111.7,63.3 112.7,63.3 113.7,63.3 117.7,63.3 118.7,63.3 119.7,63.3 120.7,63.3 121.7,63.3 122.7,63.3 125.7,63.3 126.7,63.3 127.7,63.3 128.7,63.3 129.7,63.3 130.7,63.3 131.7,63.3 132.7,63.3 133.7,63.3 134.7,63.3 138.2,63.3 140.7,63.3 143.7,63.3 145.7,63.3 146.7,63.3 147.7,63.3 148.7,63.3 149.7,63.3 159.7,63.3 160.7,63.3 161.7,63.3 162.7,63.3 163.7,63.3 164.7,63.3 183.7,63.3 184.7,63.3 186.7,63.3 187.7,63.3 188.7,63.3 189.7,63.3 190.7,63.3 191.7,63.3 192.7,63.3 193.7,63.3 194.7,63.3 195.7,63.3 196.7,63.3 197.7,63.3 198.7,63.3 199.7,63.3 200.7,63.3 201.7,63.3 202.7,63.3 203.7,63.3 204.7,63.3 205.7,63.3 206.7,63.3 207.7,63.3 208.7,63.3 209.7,63.3 210.7,63.3 211.7,63.3 212.7,63.3 213.7,63.3 214.7,63.3 215.7,63.3 216.7,63.3 217.7,63.3 218.7,63.3 219.7,63.3 220.7,63.3 221.7,63.3 222.7,63.3 223.7,63.3 224.7,63.3 225.7,63.3 226.7,63.3 227.7,63.3 228.7,63.3 229.7,63.3 230.7,63.3 231.7,63.3 232.7,63.3 233.7,63.3 234.7,63.3 235.7,63.3 236.7,63.3 237.7,63.3 238.7,63.3 239.7,63.3 240.7,63.3 241.7,63.3 242.7,63.3 243.7,63.3 244.7,63.3 245.7,63.3 246.7,63.3 247.7,63.3 248.7,63.3 249.7,63.3 250.7,63.3 251.7,63.3 252.7,63.3 253.7,63.3 254.7,63.3 255.7,63.3 256.7,63.3 257.7,63.3 258.7,63.3 259.7,63.3 260.7,63.3 261.7,63.3 262.7,63.3 263.7,63.3 264.7,63.3 265.7,63.3 266.7,63.3 267.7,63.3 268.7,63.3 269.7,63.3 270.7,63.3 271.7,63.3 272.7,63.3 273.7,63.3 274.7,63.3 275.7,63.3 276.7,63.3 279.7,63.3 280.7,63.3 281.7,63.3 282.7,63.3 283.7,63.3 284.7,63.3 285.7,63.3 306.2,63.3 14.179,63.321 21.664,63.336 407.075,63.55 168.236,63.764 165.7,63.8 173.2,63.8 337.2,63.8 409.075,63.8 410.075,63.8 411.2,63.8 412.325,63.8 413.7,63.8 16.593,63.907 408.075,63.925 13.472,64.028 20.957,64.043 137.7,64.3 138.7,64.3 140.7,64.3 143.7,64.3 145.7,64.3 170.2,64.3 184.7,64.3 186.7,64.3 190.7,64.3 191.7,64.3 192.7,64.3 193.7,64.3 194.7,64.3 195.7,64.3 196.7,64.3 197.7,64.3 198.7,64.3 199.7,64.3 200.7,64.3 201.7,64.3 202.7,64.3 203.7,64.3 204.7,64.3 205.7,64.3 206.7,64.3 207.7,64.3 208.7,64.3 209.7,64.3 210.7,64.3 211.7,64.3 212.7,64.3 213.7,64.3 214.7,64.3 215.7,64.3 216.7,64.3 217.7,64.3 218.7,64.3 219.7,64.3 220.7,64.3 221.7,64.3 222.7,64.3 223.7,64.3 224.7,64.3 225.7,64.3 226.7,64.3 227.7,64.3 228.7,64.3 229.7,64.3 230.7,64.3 231.7,64.3 232.7,64.3 233.7,64.3 234.7,64.3 235.7,64.3 236.7,64.3 237.7,64.3 238.7,64.3 239.7,64.3 240.7,64.3 241.7,64.3 242.7,64.3 243.7,64.3 244.7,64.3 245.7,64.3 246.7,64.3 247.7,64.3 248.7,64.3 249.7,64.3 250.7,64.3 251.7,64.3 252.7,64.3 253.7,64.3 254.7,64.3 255.7,64.3 256.7,64.3 257.7,64.3 258.7,64.3 259.7,64.3 260.7,64.3 261.7,64.3 262.7,64.3 263.7,64.3 264.7,64.3 265.7,64.3 266.7,64.3 267.7,64.3 268.7,64.3 269.7,64.3 270.7,64.3 271.7,64.3 272.7,64.3 273.7,64.3 274.7,64.3 275.7,64.3 278.7,64.3 305.7,64.3 167.528,64.472 15.886,64.614 12.765,64.735 20.25,64.75 164.7,64.8 173.7,64.8 174.7,64.8 175.7,64.8 176.7,64.8 177.7,64.8 178.7,64.8 179.7,64.8 180.7,64.8 181.7,64.8 182.7,64.8 183.7,64.8 189.7,64.8 308.2,64.8 309.2,64.8 310.2,64.8 312.7,64.8 313.7,64.8 314.7,64.8 315.7,64.8 316.7,64.8 317.7,64.8 318.7,64.8 319.7,64.8 320.7,64.8 321.7,64.8 322.7,64.8 323.7,64.8 324.7,64.8 325.7,64.8 326.7,64.8 327.7,64.8 328.7,64.8 329.7,64.8 330.7,64.8 331.7,64.8 332.7,64.8 334.7,64.8 337.7,64.8 166.821,65.179 168.321,65.179 22.7,65.3 23.7,65.3 24.7,65.3 25.7,65.3 26.7,65.3 27.7,65.3 28.7,65.3 29.7,65.3 30.7,65.3 31.7,65.3 32.7,65.3 33.7,65.3 34.7,65.3 35.7,65.3 36.7,65.3 37.7,65.3 38.7,65.3 39.7,65.3 40.7,65.3 41.7,65.3 42.7,65.3 43.7,65.3 44.7,65.3 45.7,65.3 46.7,65.3 47.7,65.3 48.7,65.3 49.7,65.3 50.7,65.3 51.7,65.3 52.7,65.3 53.7,65.3 54.7,65.3 55.7,65.3 56.7,65.3 57.7,65.3 58.7,65.3 59.7,65.3 60.7,65.3 61.7,65.3 62.7,65.3 63.7,65.3 64.7,65.3 65.7,65.3 66.7,65.3 67.7,65.3 71.7,65.3 72.7,65.3 73.7,65.3 74.7,65.3 75.7,65.3 76.7,65.3 77.7,65.3 78.7,65.3 79.7,65.3 80.7,65.3 81.7,65.3 82.7,65.3 83.7,65.3 84.7,65.3 85.7,65.3 86.7,65.3 87.7,65.3 88.7,65.3 89.7,65.3 90.7,65.3 91.7,65.3 92.7,65.3 93.7,65.3 94.7,65.3 95.7,65.3 96.7,65.3 97.7,65.3 98.7,65.3 99.7,65.3 100.7,65.3 101.7,65.3 102.7,65.3 103.7,65.3 104.7,65.3 105.7,65.3 106.7,65.3 107.7,65.3 108.7,65.3 109.7,65.3 110.7,65.3 111.7,65.3 112.7,65.3 113.7,65.3 114.7,65.3 115.7,65.3 119.7,65.3 120.7,65.3 121.7,65.3 122.7,65.3 123.7,65.3 124.7,65.3 127.7,65.3 128.7,65.3 129.7,65.3 130.7,65.3 131.7,65.3 132.7,65.3 133.7,65.3 134.7,65.3 135.7,65.3 136.7,65.3 137.7,65.3 138.7,65.3 140.7,65.3 143.7,65.3 146.7,65.3 147.7,65.3 148.7,65.3 149.7,65.3 150.7,65.3 151.7,65.3 152.7,65.3 153.7,65.3 154.7,65.3 155.7,65.3 156.7,65.3 157.7,65.3 158.7,65.3 159.7,65.3 160.7,65.3 161.7,65.3 162.7,65.3 163.7,65.3 170.2,65.3 171.2,65.3 186.7,65.3 277.7,65.3 305.7,65.3 333.7,65.3 15.179,65.321 12.058,65.442 19.543,65.457 70.486,65.639 116.7,65.8 188.7,65.8 307.7,65.8 310.7,65.8 335.7,65.8 337.7,65.8 166.114,65.886 167.614,65.886 14.472,66.028 11.351,66.149 18.836,66.164 120.2,66.3 125.7,66.3 170.2,66.3 172.2,66.3 186.2,66.3 191.2,66.3 192.2,66.3 193.2,66.3 194.2,66.3 195.2,66.3 196.2,66.3 197.2,66.3 198.2,66.3 199.2,66.3 200.2,66.3 201.2,66.3 202.2,66.3 203.2,66.3 204.2,66.3 205.2,66.3 206.2,66.3 207.2,66.3 208.2,66.3 209.2,66.3 210.2,66.3 211.2,66.3 212.2,66.3 213.2,66.3 214.2,66.3 215.2,66.3 216.2,66.3 217.2,66.3 218.2,66.3 219.2,66.3 220.2,66.3 221.2,66.3 222.2,66.3 223.2,66.3 224.2,66.3 225.2,66.3 226.2,66.3 227.2,66.3 228.2,66.3 229.2,66.3 230.2,66.3 231.2,66.3 232.2,66.3 233.2,66.3 234.2,66.3 235.2,66.3 236.2,66.3 237.2,66.3 238.2,66.3 239.2,66.3 240.2,66.3 241.2,66.3 242.2,66.3 243.2,66.3 244.2,66.3 245.2,66.3 246.2,66.3 247.2,66.3 248.2,66.3 249.2,66.3 250.2,66.3 251.2,66.3 252.2,66.3 253.2,66.3 254.2,66.3 255.2,66.3 256.2,66.3 257.2,66.3 258.2,66.3 259.2,66.3 260.2,66.3 261.2,66.3 262.2,66.3 263.2,66.3 264.2,66.3 265.2,66.3 266.2,66.3 267.2,66.3 268.2,66.3 269.2,66.3 270.2,66.3 271.2,66.3 272.2,66.3 273.2,66.3 274.2,66.3 275.2,66.3 276.2,66.3 277.2,66.3 305.7,66.3 334.2,66.3 21.685,66.315 69.778,66.347 165.407,66.593 166.907,66.593 13.765,66.735 31.2,66.8 32.2,66.8 33.2,66.8 34.2,66.8 35.2,66.8 36.2,66.8 37.2,66.8 38.2,66.8 39.2,66.8 40.2,66.8 41.2,66.8 42.2,66.8 43.2,66.8 44.2,66.8 45.2,66.8 46.2,66.8 47.2,66.8 48.2,66.8 49.2,66.8 50.2,66.8 51.2,66.8 52.2,66.8 53.2,66.8 54.2,66.8 55.2,66.8 56.2,66.8 57.2,66.8 58.2,66.8 59.2,66.8 60.2,66.8 61.2,66.8 62.2,66.8 63.2,66.8 64.2,66.8 65.2,66.8 66.2,66.8 117.7,66.8 121.2,66.8 187.7,66.8 307.7,66.8 311.2,66.8 312.2,66.8 313.2,66.8 314.2,66.8 315.2,66.8 316.2,66.8 317.2,66.8 318.2,66.8 319.2,66.8 320.2,66.8 321.2,66.8 322.2,66.8 323.2,66.8 324.2,66.8 325.2,66.8 326.2,66.8 327.2,66.8 328.2,66.8 329.2,66.8 330.2,66.8 331.2,66.8 335.7,66.8 337.7,66.8 10.644,66.856 18.129,66.871 20.978,67.022 69.071,67.054 126.7,67.3 127.7,67.3 128.7,67.3 129.7,67.3 130.7,67.3 131.7,67.3 132.7,67.3 133.7,67.3 134.7,67.3 135.7,67.3 136.7,67.3 137.7,67.3 138.7,67.3 140.7,67.3 143.7,67.3 144.7,67.3 145.7,67.3 148.7,67.3 149.7,67.3 150.7,67.3 151.7,67.3 152.7,67.3 153.7,67.3 154.7,67.3 155.7,67.3 156.7,67.3 157.7,67.3 158.7,67.3 159.7,67.3 160.7,67.3 161.7,67.3 162.7,67.3 163.7,67.3 164.7,67.3 166.2,67.3 169.7,67.3 170.7,67.3 171.7,67.3 172.7,67.3 173.7,67.3 174.7,67.3 175.7,67.3 176.7,67.3 177.7,67.3 178.7,67.3 179.7,67.3 180.7,67.3 181.7,67.3 182.7,67.3 183.7,67.3 184.7,67.3 185.7,67.3 186.7,67.3 190.2,67.3 191.2,67.3 192.2,67.3 193.2,67.3 194.2,67.3 195.2,67.3 196.2,67.3 197.2,67.3 198.2,67.3 199.2,67.3 200.2,67.3 201.2,67.3 202.2,67.3 203.2,67.3 204.2,67.3 205.2,67.3 206.2,67.3 207.2,67.3 208.2,67.3 209.2,67.3 210.2,67.3 211.2,67.3 212.2,67.3 213.2,67.3 214.2,67.3 215.2,67.3 216.2,67.3 217.2,67.3 218.2,67.3 219.2,67.3 220.2,67.3 221.2,67.3 222.2,67.3 223.2,67.3 224.2,67.3 225.2,67.3 226.2,67.3 227.2,67.3 228.2,67.3 229.2,67.3 230.2,67.3 231.2,67.3 232.2,67.3 233.2,67.3 234.2,67.3 235.2,67.3 236.2,67.3 237.2,67.3 238.2,67.3 239.2,67.3 240.2,67.3 241.2,67.3 242.2,67.3 243.2,67.3 244.2,67.3 245.2,67.3 246.2,67.3 247.2,67.3 248.2,67.3 249.2,67.3 250.2,67.3 251.2,67.3 252.2,67.3 253.2,67.3 254.2,67.3 255.2,67.3 256.2,67.3 257.2,67.3 258.2,67.3 259.2,67.3 260.2,67.3 261.2,67.3 262.2,67.3 263.2,67.3 264.2,67.3 265.2,67.3 266.2,67.3 267.2,67.3 268.2,67.3 269.2,67.3 270.2,67.3 271.2,67.3 272.2,67.3 273.2,67.3 274.2,67.3 275.2,67.3 276.2,67.3 277.2,67.3 278.2,67.3 279.2,67.3 280.2,67.3 281.2,67.3 282.2,67.3 283.2,67.3 284.2,67.3 285.2,67.3 286.2,67.3 287.2,67.3 288.2,67.3 289.2,67.3 290.2,67.3 291.2,67.3 292.2,67.3 293.2,67.3 294.2,67.3 295.2,67.3 296.2,67.3 297.2,67.3 298.2,67.3 299.2,67.3 300.2,67.3 301.2,67.3 302.2,67.3 303.2,67.3 304.2,67.3 305.2,67.3 332.2,67.3 334.2,67.3 13.058,67.442 118.407,67.507 121.907,67.507 9.937,67.563 17.422,67.578 20.271,67.729 68.364,67.761 308.2,67.8 313.2,67.8 314.2,67.8 315.2,67.8 316.2,67.8 317.2,67.8 318.2,67.8 319.2,67.8 320.2,67.8 321.2,67.8 322.2,67.8 323.2,67.8 324.2,67.8 325.2,67.8 326.2,67.8 327.2,67.8 328.2,67.8 329.2,67.8 330.2,67.8 335.7,67.8 337.7,67.8 30.493,68.007 12.351,68.149 119.114,68.214 122.614,68.214 9.229,68.271 16.715,68.285 138.7,68.3 140.7,68.3 143.7,68.3 146.7,68.3 334.2,68.3 19.564,68.436 67.657,68.468 29.786,68.714 32.7,68.8 33.7,68.8 34.7,68.8 35.7,68.8 36.7,68.8 37.7,68.8 38.7,68.8 39.7,68.8 40.7,68.8 41.7,68.8 42.7,68.8 43.7,68.8 44.7,68.8 45.7,68.8 46.7,68.8 47.7,68.8 48.7,68.8 49.7,68.8 50.7,68.8 51.7,68.8 52.7,68.8 53.7,68.8 54.7,68.8 55.7,68.8 56.7,68.8 57.7,68.8 58.7,68.8 59.7,68.8 60.7,68.8 61.7,68.8 62.7,68.8 63.7,68.8 64.7,68.8 65.7,68.8 66.7,68.8 308.2,68.8 313.7,68.8 335.7,68.8 337.7,68.8 11.644,68.856 119.821,68.921 123.321,68.921 8.522,68.978 16.008,68.992 18.857,69.143 74.7,69.3 75.7,69.3 76.7,69.3 77.7,69.3 78.7,69.3 79.7,69.3 80.7,69.3 81.7,69.3 82.7,69.3 83.7,69.3 84.7,69.3 85.7,69.3 86.7,69.3 87.7,69.3 88.7,69.3 89.7,69.3 90.7,69.3 91.7,69.3 92.7,69.3 93.7,69.3 94.7,69.3 95.7,69.3 96.7,69.3 97.7,69.3 98.7,69.3 99.7,69.3 100.7,69.3 101.7,69.3 124.2,69.3 125.2,69.3 126.2,69.3 127.2,69.3 128.2,69.3 129.2,69.3 130.2,69.3 131.2,69.3 132.2,69.3 133.2,69.3 134.2,69.3 135.2,69.3 136.2,69.3 137.2,69.3 138.7,69.3 140.7,69.3 144.2,69.3 145.2,69.3 146.2,69.3 147.2,69.3 148.2,69.3 149.2,69.3 150.2,69.3 151.2,69.3 152.2,69.3 153.2,69.3 154.2,69.3 155.2,69.3 156.2,69.3 157.2,69.3 158.2,69.3 159.2,69.3 160.2,69.3 161.2,69.3 162.2,69.3 163.2,69.3 164.2,69.3 167.2,69.3 168.2,69.3 169.2,69.3 170.2,69.3 171.2,69.3 172.2,69.3 173.2,69.3 174.2,69.3 175.2,69.3 176.2,69.3 177.2,69.3 178.2,69.3 179.2,69.3 180.2,69.3 181.2,69.3 182.2,69.3 183.2,69.3 184.2,69.3 185.2,69.3 188.2,69.3 189.2,69.3 190.2,69.3 191.2,69.3 192.2,69.3 193.2,69.3 194.2,69.3 195.2,69.3 196.2,69.3 197.2,69.3 198.2,69.3 199.2,69.3 200.2,69.3 201.2,69.3 202.2,69.3 203.2,69.3 204.2,69.3 205.2,69.3 206.2,69.3 207.2,69.3 208.2,69.3 209.2,69.3 210.2,69.3 211.2,69.3 212.2,69.3 213.2,69.3 214.2,69.3 215.2,69.3 216.2,69.3 217.2,69.3 218.2,69.3 219.2,69.3 220.2,69.3 221.2,69.3 222.2,69.3 223.2,69.3 224.2,69.3 225.2,69.3 226.2,69.3 227.2,69.3 228.2,69.3 229.2,69.3 230.2,69.3 231.2,69.3 232.2,69.3 233.2,69.3 234.2,69.3 235.2,69.3 236.2,69.3 237.2,69.3 238.2,69.3 239.2,69.3 240.2,69.3 241.2,69.3 242.2,69.3 243.2,69.3 244.2,69.3 245.2,69.3 246.2,69.3 247.2,69.3 248.2,69.3 249.2,69.3 250.2,69.3 251.2,69.3 252.2,69.3 253.2,69.3 254.2,69.3 255.2,69.3 256.2,69.3 257.2,69.3 258.2,69.3 259.2,69.3 260.2,69.3 261.2,69.3 262.2,69.3 263.2,69.3 264.2,69.3 265.2,69.3 266.2,69.3 267.2,69.3 268.2,69.3 269.2,69.3 270.2,69.3 271.2,69.3 272.2,69.3 273.2,69.3 274.2,69.3 275.2,69.3 276.2,69.3 277.2,69.3 278.2,69.3 279.2,69.3 280.2,69.3 281.2,69.3 282.2,69.3 283.2,69.3 284.2,69.3 285.2,69.3 286.2,69.3 287.2,69.3 288.2,69.3 289.2,69.3 290.2,69.3 291.2,69.3 292.2,69.3 293.2,69.3 294.2,69.3 295.2,69.3 296.2,69.3 297.2,69.3 298.2,69.3 299.2,69.3 300.2,69.3 301.2,69.3 302.2,69.3 303.2,69.3 304.2,69.3 305.2,69.3 333.7,69.3 29.079,69.421 31.993,69.507 10.937,69.563 120.528,69.628 7.815,69.685 73.443,69.682 15.301,69.699 306.2,69.8 307.2,69.8 308.2,69.8 313.2,69.8 315.7,69.8 316.7,69.8 317.7,69.8 318.7,69.8 319.7,69.8 320.7,69.8 321.7,69.8 322.7,69.8 323.7,69.8 324.7,69.8 325.7,69.8 326.7,69.8 327.7,69.8 328.7,69.8 329.7,69.8 330.7,69.8 331.7,69.8 332.7,69.8 334.7,69.8 337.7,69.8 18.15,69.85 28.372,70.128 31.286,70.214 10.229,70.271 185.7,70.3 188.2,70.3 333.7,70.3 121.236,70.336 7.108,70.392 72.736,70.389 14.593,70.407 17.443,70.557 313.2,70.8 315.2,70.8 318.2,70.8 337.2,70.8 30.579,70.921 9.522,70.978 121.943,71.043 6.401,71.099 72.028,71.097 13.886,71.114 16.736,71.264 75.2,71.3 76.2,71.3 77.2,71.3 78.2,71.3 79.2,71.3 80.2,71.3 81.2,71.3 82.2,71.3 83.2,71.3 84.2,71.3 85.2,71.3 86.2,71.3 87.2,71.3 88.2,71.3 89.2,71.3 90.2,71.3 91.2,71.3 92.2,71.3 93.2,71.3 94.2,71.3 95.2,71.3 96.2,71.3 97.2,71.3 98.2,71.3 99.2,71.3 100.2,71.3 123.2,71.3 124.2,71.3 125.2,71.3 126.2,71.3 127.2,71.3 128.2,71.3 129.2,71.3 130.2,71.3 131.2,71.3 132.2,71.3 133.2,71.3 134.2,71.3 135.2,71.3 136.2,71.3 137.2,71.3 138.7,71.3 140.7,71.3 141.7,71.3 142.7,71.3 146.7,71.3 147.7,71.3 148.7,71.3 149.7,71.3 150.7,71.3 151.7,71.3 152.7,71.3 153.7,71.3 154.7,71.3 155.7,71.3 156.7,71.3 157.7,71.3 158.7,71.3 159.7,71.3 160.7,71.3 161.7,71.3 162.7,71.3 163.7,71.3 164.7,71.3 165.7,71.3 166.7,71.3 167.7,71.3 168.7,71.3 169.7,71.3 170.7,71.3 171.7,71.3 172.7,71.3 173.7,71.3 174.7,71.3 175.7,71.3 176.7,71.3 177.7,71.3 178.7,71.3 179.7,71.3 180.7,71.3 181.7,71.3 182.7,71.3 183.7,71.3 184.7,71.3 185.7,71.3 187.7,71.3 188.7,71.3 189.7,71.3 190.7,71.3 191.7,71.3 192.7,71.3 193.7,71.3 194.7,71.3 195.7,71.3 196.7,71.3 197.7,71.3 198.7,71.3 199.7,71.3 200.7,71.3 201.7,71.3 202.7,71.3 203.7,71.3 204.7,71.3 205.7,71.3 206.7,71.3 207.7,71.3 208.7,71.3 209.7,71.3 210.7,71.3 211.7,71.3 212.7,71.3 213.7,71.3 214.7,71.3 215.7,71.3 216.7,71.3 217.7,71.3 218.7,71.3 219.7,71.3 220.7,71.3 221.7,71.3 222.7,71.3 223.7,71.3 224.7,71.3 225.7,71.3 226.7,71.3 227.7,71.3 228.7,71.3 229.7,71.3 230.7,71.3 231.7,71.3 232.7,71.3 233.7,71.3 234.7,71.3 235.7,71.3 236.7,71.3 237.7,71.3 238.7,71.3 239.7,71.3 240.7,71.3 241.7,71.3 242.7,71.3 243.7,71.3 244.7,71.3 245.7,71.3 246.7,71.3 247.7,71.3 248.7,71.3 249.7,71.3 250.7,71.3 251.7,71.3 252.7,71.3 253.7,71.3 254.7,71.3 255.7,71.3 256.7,71.3 257.7,71.3 258.7,71.3 259.7,71.3 260.7,71.3 261.7,71.3 262.7,71.3 263.7,71.3 264.7,71.3 265.7,71.3 266.7,71.3 267.7,71.3 268.7,71.3 269.7,71.3 270.7,71.3 271.7,71.3 272.7,71.3 273.7,71.3 274.7,71.3 275.7,71.3 276.7,71.3 277.7,71.3 278.7,71.3 279.7,71.3 280.7,71.3 281.7,71.3 282.7,71.3 283.7,71.3 284.7,71.3 285.7,71.3 286.7,71.3 287.7,71.3 288.7,71.3 289.7,71.3 27.528,71.472 8.815,71.685 74.361,71.764 5.694,71.806 71.321,71.804 143.7,71.8 313.2,71.8 315.2,71.8 317.7,71.8 336.7,71.8 13.179,71.821 16.028,71.972 69.7,72.175 29.7,72.3 30.7,72.3 31.7,72.3 32.7,72.3 33.7,72.3 34.7,72.3 35.7,72.3 36.7,72.3 37.7,72.3 38.7,72.3 39.7,72.3 40.7,72.3 41.7,72.3 42.7,72.3 43.7,72.3 44.7,72.3 45.7,72.3 46.7,72.3 47.7,72.3 48.7,72.3 49.7,72.3 50.7,72.3 51.7,72.3 52.7,72.3 53.7,72.3 54.7,72.3 55.7,72.3 56.7,72.3 57.7,72.3 58.7,72.3 59.7,72.3 60.7,72.3 61.7,72.3 62.7,72.3 63.7,72.3 64.7,72.3 65.7,72.3 66.7,72.3 67.7,72.3 68.7,72.3 138.7,72.3 140.7,72.3 290.2,72.3 320.7,72.3 321.7,72.3 322.7,72.3 323.7,72.3 324.7,72.3 325.7,72.3 326.7,72.3 327.7,72.3 328.7,72.3 329.7,72.3 330.7,72.3 331.7,72.3 332.7,72.3 333.7,72.3 334.7,72.3 335.7,72.3 8.108,72.392 27.528,72.472 73.653,72.472 4.987,72.513 12.472,72.528 70.614,72.511 144.45,72.55 15.321,72.679 3.7,72.8 313.2,72.8 315.2,72.8 317.7,72.8 7.401,73.099 72.946,73.179 11.765,73.235 69.907,73.218 29.7,73.3 125.2,73.3 126.2,73.3 127.2,73.3 128.2,73.3 129.2,73.3 130.2,73.3 131.2,73.3 132.2,73.3 133.2,73.3 134.2,73.3 135.2,73.3 136.2,73.3 137.2,73.3 138.2,73.3 140.7,73.3 145.2,73.3 146.2,73.3 147.2,73.3 148.2,73.3 149.2,73.3 150.2,73.3 151.2,73.3 152.2,73.3 153.2,73.3 154.2,73.3 155.2,73.3 156.2,73.3 157.2,73.3 158.2,73.3 159.2,73.3 160.2,73.3 161.2,73.3 162.2,73.3 163.2,73.3 164.2,73.3 165.2,73.3 166.2,73.3 167.2,73.3 168.2,73.3 169.2,73.3 170.2,73.3 171.2,73.3 172.2,73.3 173.2,73.3 174.2,73.3 175.2,73.3 176.2,73.3 177.2,73.3 178.2,73.3 179.2,73.3 180.2,73.3 181.2,73.3 182.2,73.3 183.2,73.3 184.2,73.3 185.2,73.3 186.2,73.3 189.7,73.3 190.7,73.3 191.7,73.3 192.7,73.3 193.7,73.3 194.7,73.3 195.7,73.3 196.7,73.3 197.7,73.3 198.7,73.3 199.7,73.3 200.7,73.3 201.7,73.3 202.7,73.3 203.7,73.3 204.7,73.3 205.7,73.3 206.7,73.3 207.7,73.3 208.7,73.3 209.7,73.3 210.7,73.3 211.7,73.3 212.7,73.3 213.7,73.3 214.7,73.3 215.7,73.3 216.7,73.3 217.7,73.3 218.7,73.3 219.7,73.3 220.7,73.3 221.7,73.3 222.7,73.3 223.7,73.3 224.7,73.3 225.7,73.3 226.7,73.3 227.7,73.3 228.7,73.3 229.7,73.3 230.7,73.3 231.7,73.3 232.7,73.3 233.7,73.3 234.7,73.3 235.7,73.3 236.7,73.3 237.7,73.3 238.7,73.3 239.7,73.3 240.7,73.3 241.7,73.3 242.7,73.3 243.7,73.3 244.7,73.3 245.7,73.3 246.7,73.3 247.7,73.3 248.7,73.3 249.7,73.3 250.7,73.3 251.7,73.3 252.7,73.3 253.7,73.3 254.7,73.3 255.7,73.3 256.7,73.3 257.7,73.3 258.7,73.3 259.7,73.3 260.7,73.3 261.7,73.3 262.7,73.3 263.7,73.3 264.7,73.3 265.7,73.3 266.7,73.3 267.7,73.3 268.7,73.3 269.7,73.3 270.7,73.3 271.7,73.3 272.7,73.3 273.7,73.3 274.7,73.3 275.7,73.3 276.7,73.3 277.7,73.3 278.7,73.3 279.7,73.3 280.7,73.3 281.7,73.3 282.7,73.3 283.7,73.3 284.7,73.3 285.7,73.3 286.7,73.3 287.7,73.3 290.2,73.3 320.2,73.3 321.2,73.3 322.2,73.3 323.2,73.3 324.2,73.3 325.2,73.3 326.2,73.3 327.2,73.3 328.2,73.3 329.2,73.3 330.2,73.3 331.2,73.3 332.2,73.3 333.2,73.3 334.2,73.3 14.614,73.386 27.528,73.472 2.95,73.55 6.694,73.806 187.2,73.8 313.2,73.8 315.2,73.8 317.7,73.8 72.239,73.886 124.45,74.05 13.907,74.093 11.2,74.3 31.7,74.3 32.7,74.3 33.7,74.3 34.7,74.3 35.7,74.3 36.7,74.3 37.7,74.3 38.7,74.3 39.7,74.3 40.7,74.3 41.7,74.3 42.7,74.3 43.7,74.3 44.7,74.3 45.7,74.3 46.7,74.3 47.7,74.3 48.7,74.3 49.7,74.3 50.7,74.3 51.7,74.3 52.7,74.3 53.7,74.3 54.7,74.3 55.7,74.3 56.7,74.3 57.7,74.3 58.7,74.3 59.7,74.3 60.7,74.3 61.7,74.3 62.7,74.3 63.7,74.3 64.7,74.3 65.7,74.3 66.7,74.3 67.7,74.3 140.7,74.3 156.95,74.3 183.7,74.3 290.2,74.3 334.7,74.3 27.528,74.472 5.987,74.513 71.532,74.593 2.865,74.635 13.2,74.8 123.7,74.8 242.7,74.8 313.2,74.8 315.2,74.8 318.2,74.8 30.825,74.925 156.2,75.05 67.821,75.179 5.28,75.22 11.2,75.3 70.825,75.3 126.2,75.3 127.2,75.3 128.2,75.3 129.2,75.3 130.2,75.3 131.2,75.3 132.2,75.3 133.2,75.3 134.2,75.3 135.2,75.3 136.2,75.3 137.2,75.3 138.2,75.3 139.2,75.3 140.2,75.3 158.7,75.3 159.7,75.3 160.7,75.3 161.7,75.3 162.7,75.3 163.7,75.3 164.7,75.3 165.7,75.3 166.7,75.3 167.7,75.3 168.7,75.3 169.7,75.3 170.7,75.3 171.7,75.3 172.7,75.3 173.7,75.3 174.7,75.3 175.7,75.3 176.7,75.3 177.7,75.3 178.7,75.3 179.7,75.3 180.7,75.3 181.7,75.3 188.7,75.3 189.7,75.3 190.7,75.3 191.7,75.3 192.7,75.3 193.7,75.3 194.7,75.3 195.7,75.3 196.7,75.3 197.7,75.3 198.7,75.3 199.7,75.3 200.7,75.3 201.7,75.3 202.7,75.3 203.7,75.3 204.7,75.3 205.7,75.3 206.7,75.3 207.7,75.3 210.7,75.3 211.7,75.3 212.7,75.3 213.7,75.3 214.7,75.3 215.7,75.3 216.7,75.3 217.7,75.3 218.7,75.3 219.7,75.3 220.7,75.3 221.7,75.3 222.7,75.3 223.7,75.3 224.7,75.3 225.7,75.3 226.7,75.3 227.7,75.3 228.7,75.3 229.7,75.3 230.7,75.3 231.7,75.3 232.7,75.3 233.7,75.3 234.7,75.3 235.7,75.3 236.7,75.3 237.7,75.3 238.7,75.3 239.7,75.3 240.7,75.3 241.7,75.3 245.7,75.3 246.7,75.3 247.7,75.3 248.7,75.3 249.7,75.3 250.7,75.3 251.7,75.3 252.7,75.3 253.7,75.3 254.7,75.3 255.7,75.3 256.7,75.3 257.7,75.3 258.7,75.3 259.7,75.3 260.7,75.3 261.7,75.3 262.7,75.3 263.7,75.3 264.7,75.3 265.7,75.3 266.7,75.3 267.7,75.3 268.7,75.3 269.7,75.3 270.7,75.3 271.7,75.3 272.7,75.3 273.7,75.3 274.7,75.3 275.7,75.3 276.7,75.3 277.7,75.3 278.7,75.3 279.7,75.3 280.7,75.3 281.7,75.3 282.7,75.3 283.7,75.3 284.7,75.3 285.7,75.3 286.7,75.3 287.7,75.3 288.7,75.3 289.7,75.3 316.2,75.3 319.2,75.3 320.2,75.3 321.2,75.3 322.2,75.3 323.2,75.3 324.2,75.3 325.2,75.3 326.2,75.3 327.2,75.3 328.2,75.3 329.2,75.3 330.2,75.3 331.2,75.3 332.2,75.3 335.7,75.3 2.158,75.342 27.528,75.472 122.95,75.55 13.2,75.8 67.114,75.886 4.573,75.927 31.2,75.925 1.451,76.049 26.821,76.179 11.2,76.3 70.318,76.307 31.993,76.593 66.407,76.593 3.865,76.635 29.325,76.675 13.286,76.886 26.114,76.886 11.2,77.3 32.7,77.3 33.7,77.3 34.7,77.3 35.7,77.3 36.7,77.3 37.7,77.3 38.7,77.3 39.7,77.3 40.7,77.3 41.7,77.3 42.7,77.3 43.7,77.3 44.7,77.3 45.7,77.3 46.7,77.3 47.7,77.3 48.7,77.3 49.7,77.3 50.7,77.3 51.7,77.3 52.7,77.3 53.7,77.3 54.7,77.3 55.7,77.3 56.7,77.3 57.7,77.3 58.7,77.3 59.7,77.3 60.7,77.3 61.7,77.3 62.7,77.3 63.7,77.3 64.7,77.3 65.7,77.3 70.318,77.307 3.158,77.342 13.993,77.593 25.407,77.593 29.325,77.675 30.286,77.886 68.114,77.886 28.321,78.179 2.7,78.3 11.7,78.3 14.7,78.3 15.7,78.3 16.7,78.3 17.7,78.3 18.7,78.3 19.7,78.3 20.7,78.3 21.7,78.3 22.7,78.3 23.7,78.3 24.7,78.3 70.318,78.307 30.993,78.593 67.407,78.593 27.614,78.886 12.407,79.007 2.7,79.3 31.7,79.3 32.7,79.3 33.7,79.3 34.7,79.3 35.7,79.3 36.7,79.3 37.7,79.3 38.7,79.3 39.7,79.3 40.7,79.3 41.7,79.3 42.7,79.3 43.7,79.3 44.7,79.3 45.7,79.3 46.7,79.3 47.7,79.3 48.7,79.3 49.7,79.3 50.7,79.3 51.7,79.3 52.7,79.3 53.7,79.3 54.7,79.3 55.7,79.3 56.7,79.3 57.7,79.3 58.7,79.3 59.7,79.3 60.7,79.3 61.7,79.3 62.7,79.3 63.7,79.3 64.7,79.3 65.7,79.3 66.7,79.3 70.318,79.307 26.907,79.593 13.114,79.714 69.611,80.014 2.7,80.3 15.2,80.3 16.2,80.3 17.2,80.3 18.2,80.3 19.2,80.3 20.2,80.3 21.2,80.3 22.2,80.3 23.2,80.3 24.2,80.3 25.2,80.3 26.2,80.3 13.821,80.421 68.903,80.722 65.7,80.8 14.528,81.128 2.7,81.3 15.7,81.3 16.7,81.3 17.7,81.3 18.7,81.3 19.7,81.3 20.7,81.3 21.7,81.3 22.7,81.3 23.7,81.3 24.7,81.3 25.7,81.3 26.7,81.3 27.7,81.3 28.7,81.3 29.7,81.3 30.7,81.3 31.7,81.3 32.7,81.3 33.7,81.3 34.7,81.3 35.7,81.3 36.7,81.3 37.7,81.3 38.7,81.3 39.7,81.3 40.7,81.3 41.7,81.3 42.7,81.3 43.7,81.3 44.7,81.3 45.7,81.3 46.7,81.3 47.7,81.3 48.7,81.3 49.7,81.3 50.7,81.3 51.7,81.3 52.7,81.3 53.7,81.3 54.7,81.3 55.7,81.3 56.7,81.3 57.7,81.3 58.7,81.3 59.7,81.3 60.7,81.3 61.7,81.3 62.7,81.3 63.7,81.3 64.7,81.3 68.196,81.429 14.993,82.007 67.489,82.136 2.7,82.3 14.286,82.714 66.782,82.843 2.7,83.3 16.7,83.3 17.7,83.3 18.7,83.3 19.7,83.3 20.7,83.3 21.7,83.3 22.7,83.3 23.7,83.3 24.7,83.3 25.7,83.3 26.7,83.3 27.7,83.3 28.7,83.3 29.7,83.3 30.7,83.3 31.7,83.3 32.7,83.3 33.7,83.3 34.7,83.3 35.7,83.3 36.7,83.3 37.7,83.3 38.7,83.3 39.7,83.3 40.7,83.3 41.7,83.3 42.7,83.3 43.7,83.3 44.7,83.3 45.7,83.3 46.7,83.3 47.7,83.3 48.7,83.3 49.7,83.3 50.7,83.3 51.7,83.3 52.7,83.3 53.7,83.3 54.7,83.3 55.7,83.3 56.7,83.3 57.7,83.3 58.7,83.3 59.7,83.3 60.7,83.3 61.7,83.3 62.7,83.3 63.7,83.3 64.7,83.3 65.7,83.3 13.579,83.421 15.993,84.007 2.7,84.3 13.2,84.55 2.7,85.3 2.7,86.3 13.2,87.05 15.2,87.05 2.7,87.3 13.2,88.05 15.2,88.05 2.7,88.3 13.2,89.05 15.2,89.05 101.7,89.3 103.7,89.3 210.075,89.3 313.2,89.425 208.45,89.925 210.075,90.175 101.7,90.3 103.7,90.3 313.2,90.425 208.45,90.925 335.825,90.925 210.075,91.175 15.2,91.3 101.7,91.3 103.7,91.3 120.825,91.425 123.575,91.425 160.45,91.425 163.7,91.425 313.2,91.425 337.7,91.675 13.2,91.8 157.075,91.8 159.7,91.925 162.825,91.925 208.45,91.925 335.825,91.925 121.575,92.05 124.325,92.175 15.2,92.3 101.7,92.3 313.2,92.425 126.227,92.49 127.227,92.49 128.227,92.49 129.227,92.49 130.243,92.505 131.243,92.505 132.243,92.505 133.243,92.505 134.243,92.505 135.243,92.505 136.243,92.505 137.345,92.505 138.345,92.505 139.345,92.505 140.345,92.505 141.345,92.505 142.345,92.505 143.345,92.505 144.335,92.505 145.335,92.505 146.335,92.505 147.335,92.505 148.335,92.505 149.335,92.505 150.335,92.505 125.2,92.55 151.325,92.55 152.325,92.55 153.325,92.55 154.325,92.55 155.325,92.55 156.325,92.55 159.075,92.675 162.075,92.675 337.7,92.675 13.2,92.8 122.2,92.8 208.45,92.925 257.325,92.925 335.825,92.925 259.45,93.175 313.825,93.175 15.2,93.3 101.7,93.3 158.45,93.3 161.325,93.425 122.95,93.55 316.7,93.55 256.7,93.675 337.7,93.675 13.2,93.8 104.2,93.8 335.95,93.925 123.825,94.05 124.825,94.05 125.825,94.05 126.825,94.05 127.825,94.05 128.825,94.05 129.825,94.05 130.841,94.065 131.841,94.065 132.841,94.065 133.841,94.065 134.841,94.065 135.841,94.065 136.841,94.065 137.943,94.065 138.943,94.065 139.943,94.065 140.943,94.065 141.943,94.065 142.943,94.065 143.943,94.065 144.933,94.065 145.933,94.065 146.933,94.065 147.933,94.065 148.933,94.065 149.933,94.065 150.933,94.065 258.825,94.05 322.2,94.05 151.923,94.11 152.923,94.11 153.923,94.11 154.923,94.11 155.923,94.11 156.923,94.11 157.923,94.11 160.7,94.175 323.2,94.175 331.45,94.175 332.45,94.175 333.575,94.175 15.2,94.3 108.95,94.3 109.95,94.3 110.95,94.3 111.95,94.3 210.45,94.3 224.2,94.3 225.2,94.3 226.2,94.3 227.2,94.3 317.45,94.3 324.45,94.3 330.45,94.3 118.25,94.375 119.375,94.375 117.325,94.425 120.325,94.425 221.2,94.425 234.95,94.425 255.95,94.425 327.7,94.425 7.575,94.55 104.7,94.55 218.075,94.55 114.325,94.675 315.325,94.675 337.7,94.675 3.2,94.8 4.2,94.8 5.2,94.8 10.2,94.8 11.2,94.8 12.2,94.8 13.2,94.8 258.2,94.8 159.95,94.925 227.95,94.925 228.95,94.925 229.95,94.925 230.95,94.925 231.95,94.925 232.95,94.925 233.95,94.925 237.95,94.925 238.95,94.925 239.95,94.925 240.95,94.925 241.95,94.925 242.95,94.925 243.95,94.925 244.95,94.925 245.95,94.925 246.95,94.925 247.95,94.925 248.95,94.925 249.95,94.925 250.95,94.925 251.95,94.925 252.95,94.925 253.95,94.925 254.95,94.925 318.325,94.925 334.45,94.925 335.45,94.925 107.2,95.05 108.2,95.05 120.95,95.05 121.95,95.05 122.95,95.05 123.95,95.05 124.95,95.05 125.95,95.05 126.95,95.05 127.95,95.05 128.95,95.05 129.95,95.05 130.95,95.05 131.95,95.05 132.95,95.05 133.95,95.05 134.954,95.054 135.954,95.054 136.954,95.054 137.954,95.054 138.954,95.054 139.954,95.054 140.954,95.054 141.95,95.05 142.95,95.05 143.95,95.05 144.95,95.05 145.95,95.05 146.95,95.05 147.95,95.05 148.934,95.054 149.934,95.054 150.934,95.054 151.934,95.054 152.934,95.054 153.934,95.054 154.934,95.054 156.075,95.05 157.075,95.05 211.075,95.05 212.075,95.05 214.325,95.05 215.325,95.05 320.95,95.05 321.825,95.05 111.325,95.175 324.7,95.175 224.2,95.3 330.7,95.3 15.075,95.425 117.2,95.425 221.2,95.425 315.95,95.425 327.7,95.425 7.575,95.55 218.2,95.55 257.575,95.55 337.325,95.55 114.325,95.675 159.2,95.675 103.2,95.8 4.575,96.05 10.45,96.05 316.7,96.05 111.325,96.175 324.7,96.175 336.575,96.175 103.95,96.3 209.2,96.3 330.7,96.3 117.2,96.425 158.45,96.425 221.2,96.425 224.2,96.425 256.95,96.425 327.7,96.425 7.575,96.55 14.45,96.55 218.2,96.55 114.325,96.675 210.075,96.675 211.075,96.675 212.075,96.675 214.325,96.675 215.325,96.675 227.825,96.675 228.95,96.675 229.95,96.675 230.95,96.675 231.95,96.675 235.95,96.675 236.95,96.675 237.95,96.675 238.95,96.675 239.95,96.675 240.95,96.675 241.95,96.675 242.95,96.675 243.95,96.675 244.95,96.675 245.95,96.675 246.95,96.675 247.95,96.675 248.95,96.675 249.95,96.675 250.95,96.675 251.95,96.675 252.95,96.675 253.95,96.675 254.95,96.675 255.95,96.675 334.575,96.675 335.575,96.675 104.7,96.8 107.2,96.8 108.2,96.8 120.575,96.8 121.575,96.8 122.575,96.8 123.575,96.8 124.575,96.8 125.575,96.8 126.575,96.8 127.575,96.8 128.575,96.8 129.575,96.8 130.575,96.8 131.575,96.8 132.575,96.8 133.575,96.8 134.575,96.8 135.575,96.8 136.575,96.8 137.575,96.8 138.575,96.8 139.575,96.8 140.575,96.8 141.575,96.8 142.575,96.8 143.575,96.8 144.575,96.8 145.575,96.8 146.575,96.8 147.575,96.8 148.552,96.807 149.552,96.807 150.552,96.807 151.552,96.807 152.552,96.807 153.552,96.807 154.552,96.807 155.575,96.8 156.575,96.8 157.575,96.8 317.45,96.8 318.575,96.8 320.825,96.8 321.825,96.8 1.2,97.05 4.575,97.05 10.45,97.175 13.7,97.425 227.2,97.425 322.825,97.425 323.825,97.425 324.825,97.425 325.825,97.425 326.825,97.425 327.825,97.425 328.825,97.425 329.825,97.425 330.825,97.425 331.825,97.425 332.825,97.425 333.825,97.425 7.575,97.55 108.95,97.55 109.95,97.55 110.95,97.55 111.95,97.55 112.95,97.55 113.95,97.55 114.95,97.55 115.95,97.55 116.95,97.55 117.95,97.55 118.95,97.55 119.95,97.55 215.95,97.55 216.95,97.55 217.95,97.55 218.95,97.55 219.95,97.55 221.075,97.55 222.2,97.55 223.325,97.55 224.325,97.55 225.2,97.55 226.2,97.55 1.575,98.05 2.575,98.05 3.575,98.05 4.575,98.05 5.7,98.175 6.7,98.175 8.45,98.175 9.575,98.175 10.7,98.175 11.825,98.175 12.95,98.175
  other v2: 447.7,1.3 448.7,1.3 449.7,1.3 450.7,1.3 451.7,1.3 452.7,1.3 453.7,1.3 454.7,1.3 455.7,1.3 456.7,1.3 459.2,1.3 461.7,1.3 463.2,1.3 457.7,2.3 458.7,3.3 450.2,5.3 451.2,5.3 452.2,5.3 453.2,5.3 454.2,5.3 455.2,5.3 456.2,5.3 449.7,6.3 453.2,6.3 449.7,7.3 452.2,7.3 446.7,8.3 447.7,8.3 448.7,8.3 449.7,8.3 451.2,8.3 459.7,12.3 460.7,12.3 459.7,13.8 459.7,14.8 459.7,15.8 452.2,16.3 459.7,16.8 452.2,17.3 456.7,17.3 459.7,17.8 455.7,18.3 456.7,18.3 426.7,18.8 427.7,18.8 428.7,18.8 429.7,18.8 430.7,18.8 431.7,18.8 432.7,18.8 433.7,18.8 441.2,18.8 449.7,18.8 450.7,18.8 451.7,18.8 452.7,18.8 453.7,18.8 454.7,18.8 459.7,18.8 442.7,19.3 456.7,19.3 434.2,19.8 441.2,19.8 443.7,19.8 444.7,19.8 445.7,19.8 449.7,19.8 459.7,19.8 456.7,20.3 434.2,20.8 441.2,20.8 445.7,20.8 446.7,20.8 447.7,20.8 448.7,20.8 449.7,20.8 459.7,20.8 456.2,21.3 434.2,21.8 435.2,21.8 436.2,21.8 437.2,21.8 438.2,21.8 439.2,21.8 440.2,21.8 441.2,21.8 443.2,21.8 444.2,21.8 445.2,21.8 446.2,21.8 447.2,21.8 448.2,21.8 449.2,21.8 450.2,21.8 451.2,21.8 452.2,21.8 453.2,21.8 454.2,21.8 455.2,21.8 459.7,21.8 433.2,22.8 434.2,22.8 435.2,22.8 436.2,22.8 437.2,22.8 438.2,22.8 439.2,22.8 440.2,22.8 441.2,22.8 458.7,22.8 443.7,23.3 457.7,23.8 444.2,24.3 455.7,24.8 456.7,24.8 443.7,25.3 449.7,25.3 450.7,25.3 451.7,25.3 452.7,25.3 453.7,25.3 454.7,25.3 436.7,25.8 437.7,25.8 438.7,25.8 439.7,25.8 440.7,25.8 441.7,25.8 442.7,25.8 443.7,26.3 444.7,26.3 445.7,26.3 454.2,38.3 456.7,38.3 461.7,38.8 454.2,39.8 455.2,39.8 456.2,39.8 457.2,39.8 409.7,40.3 410.7,40.3 411.7,40.3 412.7,40.3 413.7,40.3 414.7,40.3 415.7,40.3 416.7,40.3 417.7,40.3 418.7,40.3 420.2,40.3 421.2,40.3 422.2,40.3 423.2,40.3 424.2,40.3 425.2,40.3 426.2,40.3 427.2,40.3 428.2,40.3 429.2,40.3 430.2,40.3 450.7,40.3 431.2,40.8 432.2,40.8 433.2,40.8 434.2,40.8 435.2,40.8 436.2,40.8 437.2,40.8 438.2,40.8 439.2,40.8 440.2,40.8 441.2,40.8 442.2,40.8 443.2,40.8 444.2,40.8 445.2,40.8 446.2,40.8 447.2,40.8 448.2,40.8 449.2,40.8 411.7,41.3 412.7,41.3 413.7,41.3 417.7,41.3 418.7,41.3 419.7,41.3 425.7,41.3 427.7,41.3 450.7,41.3 464.2,41.3 435.2,41.8 417.7,42.3 418.7,42.3 419.7,42.3 425.7,42.3 427.7,42.3 450.7,42.3 435.2,42.8 451.7,42.8 453.2,42.8 454.2,42.8 455.2,42.8 456.2,42.8 457.2,42.8 417.7,43.3 418.7,43.3 419.7,43.3 425.7,43.3 427.7,43.3 431.2,43.8 432.2,43.8 433.2,43.8 434.2,43.8 435.2,43.8 461.7,43.8 412.7,44.3 413.7,44.3 417.7,44.3 418.7,44.3 419.7,44.3 425.7,44.3 426.7,44.3 427.7,44.3 431.2,44.8 430.7,45.8 459.2,48.3 461.7,48.3 464.2,48.3 466.7,48.3 466.7,50.8 466.7,53.3 466.7,55.8 466.7,58.3 456.7,60.8 459.2,60.8 464.2,60.8 466.7,60.8 459.2,63.3 461.7,63.3 464.2,63.3 466.7,63.3 461.7,65.8 464.2,65.8 459.2,68.3 461.7,68.3 464.2,68.3 459.2,70.8 461.7,70.8 468.7,70.8 459.2,73.3 468.7,73.3 454.2,75.8 456.7,75.8 459.2,75.8 461.7,75.8 468.7,75.8 459.2,78.3 461.7,78.3 464.2,78.3 466.7,78.3 468.7,78.3 451.7,80.8 459.2,80.8 461.7,80.8 468.7,80.8 444.2,83.3 446.7,83.3 449.2,83.3 451.7,83.3 459.2,83.3 461.7,83.3 468.7,83.3 446.7,85.8 449.2,85.8 451.7,85.8 454.2,85.8 456.7,85.8 459.2,85.8 461.7,85.8 464.2,85.8 466.7,85.8 468.7,85.8 451.7,91.3 454.2,91.3 456.7,91.3
  other v3: 436.787,33.466 441.613,33.466 436.287,46.966 441.113,46.966
  other v4: 438.184,33.593 440.216,33.593 437.803,34.736 440.597,34.736 437.803,36.133 440.597,36.133 437.684,47.093 439.716,47.093 437.303,48.236 440.097,48.236 437.303,49.633 440.097,49.633
  other v5: 25.4,3.175 60.325,3.175 167.005,3.175 273.685,3.175 380.365,3.175 466.725,3.175 25.4,98.425 60.325,98.425 167.005,98.425 273.685,98.425 380.365,98.425 466.725,98.425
